# OpenTallas memory compiler (tools/mem_compiler), ASAP7 abstract view
VERSION 5.7 ;
BUSBITCHARS "[]" ;
DIVIDERCHAR "/" ;
PROPERTYDEFINITIONS
  MACRO width INTEGER ;
  MACRO depth INTEGER ;
  MACRO banks INTEGER ;
END PROPERTYDEFINITIONS
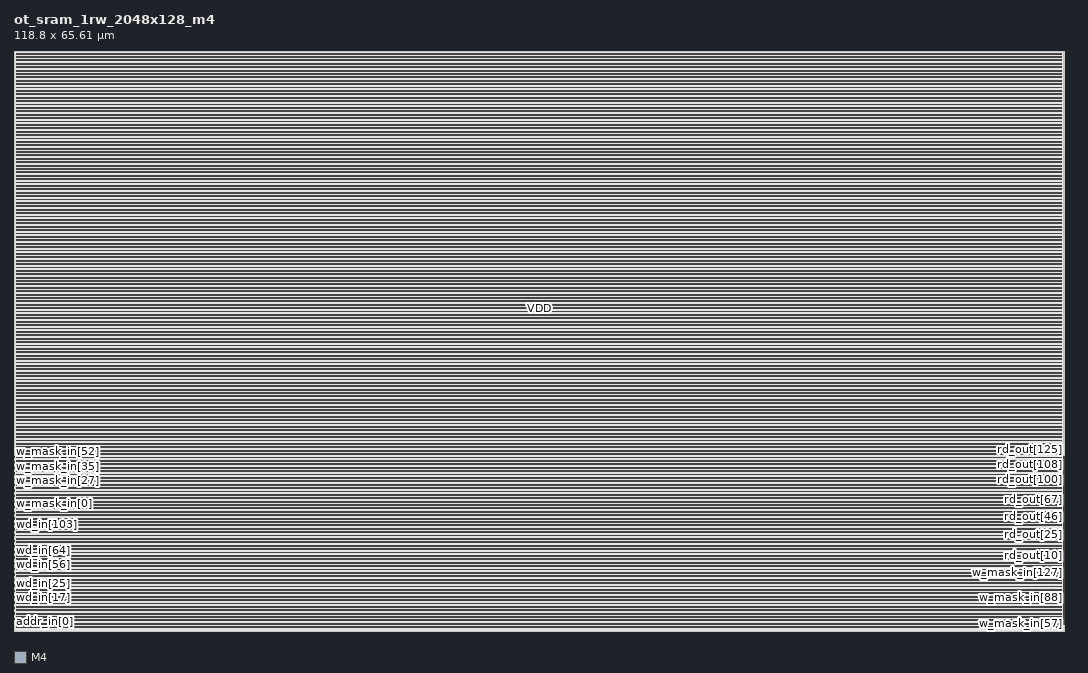
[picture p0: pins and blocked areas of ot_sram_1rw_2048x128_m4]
MACRO ot_sram_1rw_2048x128_m4
  PROPERTY width 128 ;
  PROPERTY depth 2048 ;
  PROPERTY banks 1 ;
  FOREIGN ot_sram_1rw_2048x128_m4 0 0 ;
  SYMMETRY X Y R90 ;
  SIZE 118.800 BY 65.610 ;
  CLASS BLOCK ;
  PIN clk
    DIRECTION INPUT ;
    USE CLOCK ;
    SHAPE ABUTMENT ;
    PORT
      LAYER M4 ;
      RECT 0.000 0.768 0.024 0.792 ;
    END
  END clk
  PIN ce_in
    DIRECTION INPUT ;
    USE SIGNAL ;
    SHAPE ABUTMENT ;
    PORT
      LAYER M4 ;
      RECT 0.000 0.864 0.024 0.888 ;
    END
  END ce_in
  PIN we_in
    DIRECTION INPUT ;
    USE SIGNAL ;
    SHAPE ABUTMENT ;
    PORT
      LAYER M4 ;
      RECT 0.000 0.960 0.024 0.984 ;
    END
  END we_in
  PIN addr_in[0]
    DIRECTION INPUT ;
    USE SIGNAL ;
    SHAPE ABUTMENT ;
    PORT
      LAYER M4 ;
      RECT 0.000 1.056 0.024 1.080 ;
    END
  END addr_in[0]
  PIN addr_in[1]
    DIRECTION INPUT ;
    USE SIGNAL ;
    SHAPE ABUTMENT ;
    PORT
      LAYER M4 ;
      RECT 0.000 1.152 0.024 1.176 ;
    END
  END addr_in[1]
  PIN addr_in[2]
    DIRECTION INPUT ;
    USE SIGNAL ;
    SHAPE ABUTMENT ;
    PORT
      LAYER M4 ;
      RECT 0.000 1.248 0.024 1.272 ;
    END
  END addr_in[2]
  PIN addr_in[3]
    DIRECTION INPUT ;
    USE SIGNAL ;
    SHAPE ABUTMENT ;
    PORT
      LAYER M4 ;
      RECT 0.000 1.344 0.024 1.368 ;
    END
  END addr_in[3]
  PIN addr_in[4]
    DIRECTION INPUT ;
    USE SIGNAL ;
    SHAPE ABUTMENT ;
    PORT
      LAYER M4 ;
      RECT 0.000 1.440 0.024 1.464 ;
    END
  END addr_in[4]
  PIN addr_in[5]
    DIRECTION INPUT ;
    USE SIGNAL ;
    SHAPE ABUTMENT ;
    PORT
      LAYER M4 ;
      RECT 0.000 1.536 0.024 1.560 ;
    END
  END addr_in[5]
  PIN addr_in[6]
    DIRECTION INPUT ;
    USE SIGNAL ;
    SHAPE ABUTMENT ;
    PORT
      LAYER M4 ;
      RECT 0.000 1.632 0.024 1.656 ;
    END
  END addr_in[6]
  PIN addr_in[7]
    DIRECTION INPUT ;
    USE SIGNAL ;
    SHAPE ABUTMENT ;
    PORT
      LAYER M4 ;
      RECT 0.000 1.728 0.024 1.752 ;
    END
  END addr_in[7]
  PIN addr_in[8]
    DIRECTION INPUT ;
    USE SIGNAL ;
    SHAPE ABUTMENT ;
    PORT
      LAYER M4 ;
      RECT 0.000 1.824 0.024 1.848 ;
    END
  END addr_in[8]
  PIN addr_in[9]
    DIRECTION INPUT ;
    USE SIGNAL ;
    SHAPE ABUTMENT ;
    PORT
      LAYER M4 ;
      RECT 0.000 1.920 0.024 1.944 ;
    END
  END addr_in[9]
  PIN addr_in[10]
    DIRECTION INPUT ;
    USE SIGNAL ;
    SHAPE ABUTMENT ;
    PORT
      LAYER M4 ;
      RECT 0.000 2.016 0.024 2.040 ;
    END
  END addr_in[10]
  PIN wd_in[0]
    DIRECTION INPUT ;
    USE SIGNAL ;
    SHAPE ABUTMENT ;
    PORT
      LAYER M4 ;
      RECT 0.000 2.112 0.024 2.136 ;
    END
  END wd_in[0]
  PIN wd_in[1]
    DIRECTION INPUT ;
    USE SIGNAL ;
    SHAPE ABUTMENT ;
    PORT
      LAYER M4 ;
      RECT 0.000 2.208 0.024 2.232 ;
    END
  END wd_in[1]
  PIN wd_in[2]
    DIRECTION INPUT ;
    USE SIGNAL ;
    SHAPE ABUTMENT ;
    PORT
      LAYER M4 ;
      RECT 0.000 2.304 0.024 2.328 ;
    END
  END wd_in[2]
  PIN wd_in[3]
    DIRECTION INPUT ;
    USE SIGNAL ;
    SHAPE ABUTMENT ;
    PORT
      LAYER M4 ;
      RECT 0.000 2.400 0.024 2.424 ;
    END
  END wd_in[3]
  PIN wd_in[4]
    DIRECTION INPUT ;
    USE SIGNAL ;
    SHAPE ABUTMENT ;
    PORT
      LAYER M4 ;
      RECT 0.000 2.496 0.024 2.520 ;
    END
  END wd_in[4]
  PIN wd_in[5]
    DIRECTION INPUT ;
    USE SIGNAL ;
    SHAPE ABUTMENT ;
    PORT
      LAYER M4 ;
      RECT 0.000 2.592 0.024 2.616 ;
    END
  END wd_in[5]
  PIN wd_in[6]
    DIRECTION INPUT ;
    USE SIGNAL ;
    SHAPE ABUTMENT ;
    PORT
      LAYER M4 ;
      RECT 0.000 2.688 0.024 2.712 ;
    END
  END wd_in[6]
  PIN wd_in[7]
    DIRECTION INPUT ;
    USE SIGNAL ;
    SHAPE ABUTMENT ;
    PORT
      LAYER M4 ;
      RECT 0.000 2.784 0.024 2.808 ;
    END
  END wd_in[7]
  PIN wd_in[8]
    DIRECTION INPUT ;
    USE SIGNAL ;
    SHAPE ABUTMENT ;
    PORT
      LAYER M4 ;
      RECT 0.000 2.880 0.024 2.904 ;
    END
  END wd_in[8]
  PIN wd_in[9]
    DIRECTION INPUT ;
    USE SIGNAL ;
    SHAPE ABUTMENT ;
    PORT
      LAYER M4 ;
      RECT 0.000 2.976 0.024 3.000 ;
    END
  END wd_in[9]
  PIN wd_in[10]
    DIRECTION INPUT ;
    USE SIGNAL ;
    SHAPE ABUTMENT ;
    PORT
      LAYER M4 ;
      RECT 0.000 3.072 0.024 3.096 ;
    END
  END wd_in[10]
  PIN wd_in[11]
    DIRECTION INPUT ;
    USE SIGNAL ;
    SHAPE ABUTMENT ;
    PORT
      LAYER M4 ;
      RECT 0.000 3.168 0.024 3.192 ;
    END
  END wd_in[11]
  PIN wd_in[12]
    DIRECTION INPUT ;
    USE SIGNAL ;
    SHAPE ABUTMENT ;
    PORT
      LAYER M4 ;
      RECT 0.000 3.264 0.024 3.288 ;
    END
  END wd_in[12]
  PIN wd_in[13]
    DIRECTION INPUT ;
    USE SIGNAL ;
    SHAPE ABUTMENT ;
    PORT
      LAYER M4 ;
      RECT 0.000 3.360 0.024 3.384 ;
    END
  END wd_in[13]
  PIN wd_in[14]
    DIRECTION INPUT ;
    USE SIGNAL ;
    SHAPE ABUTMENT ;
    PORT
      LAYER M4 ;
      RECT 0.000 3.456 0.024 3.480 ;
    END
  END wd_in[14]
  PIN wd_in[15]
    DIRECTION INPUT ;
    USE SIGNAL ;
    SHAPE ABUTMENT ;
    PORT
      LAYER M4 ;
      RECT 0.000 3.552 0.024 3.576 ;
    END
  END wd_in[15]
  PIN wd_in[16]
    DIRECTION INPUT ;
    USE SIGNAL ;
    SHAPE ABUTMENT ;
    PORT
      LAYER M4 ;
      RECT 0.000 3.648 0.024 3.672 ;
    END
  END wd_in[16]
  PIN wd_in[17]
    DIRECTION INPUT ;
    USE SIGNAL ;
    SHAPE ABUTMENT ;
    PORT
      LAYER M4 ;
      RECT 0.000 3.744 0.024 3.768 ;
    END
  END wd_in[17]
  PIN wd_in[18]
    DIRECTION INPUT ;
    USE SIGNAL ;
    SHAPE ABUTMENT ;
    PORT
      LAYER M4 ;
      RECT 0.000 3.840 0.024 3.864 ;
    END
  END wd_in[18]
  PIN wd_in[19]
    DIRECTION INPUT ;
    USE SIGNAL ;
    SHAPE ABUTMENT ;
    PORT
      LAYER M4 ;
      RECT 0.000 3.936 0.024 3.960 ;
    END
  END wd_in[19]
  PIN wd_in[20]
    DIRECTION INPUT ;
    USE SIGNAL ;
    SHAPE ABUTMENT ;
    PORT
      LAYER M4 ;
      RECT 0.000 4.032 0.024 4.056 ;
    END
  END wd_in[20]
  PIN wd_in[21]
    DIRECTION INPUT ;
    USE SIGNAL ;
    SHAPE ABUTMENT ;
    PORT
      LAYER M4 ;
      RECT 0.000 4.128 0.024 4.152 ;
    END
  END wd_in[21]
  PIN wd_in[22]
    DIRECTION INPUT ;
    USE SIGNAL ;
    SHAPE ABUTMENT ;
    PORT
      LAYER M4 ;
      RECT 0.000 4.224 0.024 4.248 ;
    END
  END wd_in[22]
  PIN wd_in[23]
    DIRECTION INPUT ;
    USE SIGNAL ;
    SHAPE ABUTMENT ;
    PORT
      LAYER M4 ;
      RECT 0.000 4.320 0.024 4.344 ;
    END
  END wd_in[23]
  PIN wd_in[24]
    DIRECTION INPUT ;
    USE SIGNAL ;
    SHAPE ABUTMENT ;
    PORT
      LAYER M4 ;
      RECT 0.000 4.416 0.024 4.440 ;
    END
  END wd_in[24]
  PIN wd_in[25]
    DIRECTION INPUT ;
    USE SIGNAL ;
    SHAPE ABUTMENT ;
    PORT
      LAYER M4 ;
      RECT 0.000 4.512 0.024 4.536 ;
    END
  END wd_in[25]
  PIN wd_in[26]
    DIRECTION INPUT ;
    USE SIGNAL ;
    SHAPE ABUTMENT ;
    PORT
      LAYER M4 ;
      RECT 0.000 4.608 0.024 4.632 ;
    END
  END wd_in[26]
  PIN wd_in[27]
    DIRECTION INPUT ;
    USE SIGNAL ;
    SHAPE ABUTMENT ;
    PORT
      LAYER M4 ;
      RECT 0.000 4.704 0.024 4.728 ;
    END
  END wd_in[27]
  PIN wd_in[28]
    DIRECTION INPUT ;
    USE SIGNAL ;
    SHAPE ABUTMENT ;
    PORT
      LAYER M4 ;
      RECT 0.000 4.800 0.024 4.824 ;
    END
  END wd_in[28]
  PIN wd_in[29]
    DIRECTION INPUT ;
    USE SIGNAL ;
    SHAPE ABUTMENT ;
    PORT
      LAYER M4 ;
      RECT 0.000 4.896 0.024 4.920 ;
    END
  END wd_in[29]
  PIN wd_in[30]
    DIRECTION INPUT ;
    USE SIGNAL ;
    SHAPE ABUTMENT ;
    PORT
      LAYER M4 ;
      RECT 0.000 4.992 0.024 5.016 ;
    END
  END wd_in[30]
  PIN wd_in[31]
    DIRECTION INPUT ;
    USE SIGNAL ;
    SHAPE ABUTMENT ;
    PORT
      LAYER M4 ;
      RECT 0.000 5.088 0.024 5.112 ;
    END
  END wd_in[31]
  PIN wd_in[32]
    DIRECTION INPUT ;
    USE SIGNAL ;
    SHAPE ABUTMENT ;
    PORT
      LAYER M4 ;
      RECT 0.000 5.184 0.024 5.208 ;
    END
  END wd_in[32]
  PIN wd_in[33]
    DIRECTION INPUT ;
    USE SIGNAL ;
    SHAPE ABUTMENT ;
    PORT
      LAYER M4 ;
      RECT 0.000 5.280 0.024 5.304 ;
    END
  END wd_in[33]
  PIN wd_in[34]
    DIRECTION INPUT ;
    USE SIGNAL ;
    SHAPE ABUTMENT ;
    PORT
      LAYER M4 ;
      RECT 0.000 5.376 0.024 5.400 ;
    END
  END wd_in[34]
  PIN wd_in[35]
    DIRECTION INPUT ;
    USE SIGNAL ;
    SHAPE ABUTMENT ;
    PORT
      LAYER M4 ;
      RECT 0.000 5.472 0.024 5.496 ;
    END
  END wd_in[35]
  PIN wd_in[36]
    DIRECTION INPUT ;
    USE SIGNAL ;
    SHAPE ABUTMENT ;
    PORT
      LAYER M4 ;
      RECT 0.000 5.568 0.024 5.592 ;
    END
  END wd_in[36]
  PIN wd_in[37]
    DIRECTION INPUT ;
    USE SIGNAL ;
    SHAPE ABUTMENT ;
    PORT
      LAYER M4 ;
      RECT 0.000 5.664 0.024 5.688 ;
    END
  END wd_in[37]
  PIN wd_in[38]
    DIRECTION INPUT ;
    USE SIGNAL ;
    SHAPE ABUTMENT ;
    PORT
      LAYER M4 ;
      RECT 0.000 5.760 0.024 5.784 ;
    END
  END wd_in[38]
  PIN wd_in[39]
    DIRECTION INPUT ;
    USE SIGNAL ;
    SHAPE ABUTMENT ;
    PORT
      LAYER M4 ;
      RECT 0.000 5.856 0.024 5.880 ;
    END
  END wd_in[39]
  PIN wd_in[40]
    DIRECTION INPUT ;
    USE SIGNAL ;
    SHAPE ABUTMENT ;
    PORT
      LAYER M4 ;
      RECT 0.000 5.952 0.024 5.976 ;
    END
  END wd_in[40]
  PIN wd_in[41]
    DIRECTION INPUT ;
    USE SIGNAL ;
    SHAPE ABUTMENT ;
    PORT
      LAYER M4 ;
      RECT 0.000 6.048 0.024 6.072 ;
    END
  END wd_in[41]
  PIN wd_in[42]
    DIRECTION INPUT ;
    USE SIGNAL ;
    SHAPE ABUTMENT ;
    PORT
      LAYER M4 ;
      RECT 0.000 6.144 0.024 6.168 ;
    END
  END wd_in[42]
  PIN wd_in[43]
    DIRECTION INPUT ;
    USE SIGNAL ;
    SHAPE ABUTMENT ;
    PORT
      LAYER M4 ;
      RECT 0.000 6.240 0.024 6.264 ;
    END
  END wd_in[43]
  PIN wd_in[44]
    DIRECTION INPUT ;
    USE SIGNAL ;
    SHAPE ABUTMENT ;
    PORT
      LAYER M4 ;
      RECT 0.000 6.336 0.024 6.360 ;
    END
  END wd_in[44]
  PIN wd_in[45]
    DIRECTION INPUT ;
    USE SIGNAL ;
    SHAPE ABUTMENT ;
    PORT
      LAYER M4 ;
      RECT 0.000 6.432 0.024 6.456 ;
    END
  END wd_in[45]
  PIN wd_in[46]
    DIRECTION INPUT ;
    USE SIGNAL ;
    SHAPE ABUTMENT ;
    PORT
      LAYER M4 ;
      RECT 0.000 6.528 0.024 6.552 ;
    END
  END wd_in[46]
  PIN wd_in[47]
    DIRECTION INPUT ;
    USE SIGNAL ;
    SHAPE ABUTMENT ;
    PORT
      LAYER M4 ;
      RECT 0.000 6.624 0.024 6.648 ;
    END
  END wd_in[47]
  PIN wd_in[48]
    DIRECTION INPUT ;
    USE SIGNAL ;
    SHAPE ABUTMENT ;
    PORT
      LAYER M4 ;
      RECT 0.000 6.720 0.024 6.744 ;
    END
  END wd_in[48]
  PIN wd_in[49]
    DIRECTION INPUT ;
    USE SIGNAL ;
    SHAPE ABUTMENT ;
    PORT
      LAYER M4 ;
      RECT 0.000 6.816 0.024 6.840 ;
    END
  END wd_in[49]
  PIN wd_in[50]
    DIRECTION INPUT ;
    USE SIGNAL ;
    SHAPE ABUTMENT ;
    PORT
      LAYER M4 ;
      RECT 0.000 6.912 0.024 6.936 ;
    END
  END wd_in[50]
  PIN wd_in[51]
    DIRECTION INPUT ;
    USE SIGNAL ;
    SHAPE ABUTMENT ;
    PORT
      LAYER M4 ;
      RECT 0.000 7.008 0.024 7.032 ;
    END
  END wd_in[51]
  PIN wd_in[52]
    DIRECTION INPUT ;
    USE SIGNAL ;
    SHAPE ABUTMENT ;
    PORT
      LAYER M4 ;
      RECT 0.000 7.104 0.024 7.128 ;
    END
  END wd_in[52]
  PIN wd_in[53]
    DIRECTION INPUT ;
    USE SIGNAL ;
    SHAPE ABUTMENT ;
    PORT
      LAYER M4 ;
      RECT 0.000 7.200 0.024 7.224 ;
    END
  END wd_in[53]
  PIN wd_in[54]
    DIRECTION INPUT ;
    USE SIGNAL ;
    SHAPE ABUTMENT ;
    PORT
      LAYER M4 ;
      RECT 0.000 7.296 0.024 7.320 ;
    END
  END wd_in[54]
  PIN wd_in[55]
    DIRECTION INPUT ;
    USE SIGNAL ;
    SHAPE ABUTMENT ;
    PORT
      LAYER M4 ;
      RECT 0.000 7.392 0.024 7.416 ;
    END
  END wd_in[55]
  PIN wd_in[56]
    DIRECTION INPUT ;
    USE SIGNAL ;
    SHAPE ABUTMENT ;
    PORT
      LAYER M4 ;
      RECT 0.000 7.488 0.024 7.512 ;
    END
  END wd_in[56]
  PIN wd_in[57]
    DIRECTION INPUT ;
    USE SIGNAL ;
    SHAPE ABUTMENT ;
    PORT
      LAYER M4 ;
      RECT 0.000 7.584 0.024 7.608 ;
    END
  END wd_in[57]
  PIN wd_in[58]
    DIRECTION INPUT ;
    USE SIGNAL ;
    SHAPE ABUTMENT ;
    PORT
      LAYER M4 ;
      RECT 0.000 7.680 0.024 7.704 ;
    END
  END wd_in[58]
  PIN wd_in[59]
    DIRECTION INPUT ;
    USE SIGNAL ;
    SHAPE ABUTMENT ;
    PORT
      LAYER M4 ;
      RECT 0.000 7.776 0.024 7.800 ;
    END
  END wd_in[59]
  PIN wd_in[60]
    DIRECTION INPUT ;
    USE SIGNAL ;
    SHAPE ABUTMENT ;
    PORT
      LAYER M4 ;
      RECT 0.000 7.872 0.024 7.896 ;
    END
  END wd_in[60]
  PIN wd_in[61]
    DIRECTION INPUT ;
    USE SIGNAL ;
    SHAPE ABUTMENT ;
    PORT
      LAYER M4 ;
      RECT 0.000 7.968 0.024 7.992 ;
    END
  END wd_in[61]
  PIN wd_in[62]
    DIRECTION INPUT ;
    USE SIGNAL ;
    SHAPE ABUTMENT ;
    PORT
      LAYER M4 ;
      RECT 0.000 8.064 0.024 8.088 ;
    END
  END wd_in[62]
  PIN wd_in[63]
    DIRECTION INPUT ;
    USE SIGNAL ;
    SHAPE ABUTMENT ;
    PORT
      LAYER M4 ;
      RECT 0.000 8.160 0.024 8.184 ;
    END
  END wd_in[63]
  PIN wd_in[64]
    DIRECTION INPUT ;
    USE SIGNAL ;
    SHAPE ABUTMENT ;
    PORT
      LAYER M4 ;
      RECT 0.000 8.256 0.024 8.280 ;
    END
  END wd_in[64]
  PIN wd_in[65]
    DIRECTION INPUT ;
    USE SIGNAL ;
    SHAPE ABUTMENT ;
    PORT
      LAYER M4 ;
      RECT 0.000 8.352 0.024 8.376 ;
    END
  END wd_in[65]
  PIN wd_in[66]
    DIRECTION INPUT ;
    USE SIGNAL ;
    SHAPE ABUTMENT ;
    PORT
      LAYER M4 ;
      RECT 0.000 8.448 0.024 8.472 ;
    END
  END wd_in[66]
  PIN wd_in[67]
    DIRECTION INPUT ;
    USE SIGNAL ;
    SHAPE ABUTMENT ;
    PORT
      LAYER M4 ;
      RECT 0.000 8.544 0.024 8.568 ;
    END
  END wd_in[67]
  PIN wd_in[68]
    DIRECTION INPUT ;
    USE SIGNAL ;
    SHAPE ABUTMENT ;
    PORT
      LAYER M4 ;
      RECT 0.000 8.640 0.024 8.664 ;
    END
  END wd_in[68]
  PIN wd_in[69]
    DIRECTION INPUT ;
    USE SIGNAL ;
    SHAPE ABUTMENT ;
    PORT
      LAYER M4 ;
      RECT 0.000 8.736 0.024 8.760 ;
    END
  END wd_in[69]
  PIN wd_in[70]
    DIRECTION INPUT ;
    USE SIGNAL ;
    SHAPE ABUTMENT ;
    PORT
      LAYER M4 ;
      RECT 0.000 8.832 0.024 8.856 ;
    END
  END wd_in[70]
  PIN wd_in[71]
    DIRECTION INPUT ;
    USE SIGNAL ;
    SHAPE ABUTMENT ;
    PORT
      LAYER M4 ;
      RECT 0.000 8.928 0.024 8.952 ;
    END
  END wd_in[71]
  PIN wd_in[72]
    DIRECTION INPUT ;
    USE SIGNAL ;
    SHAPE ABUTMENT ;
    PORT
      LAYER M4 ;
      RECT 0.000 9.024 0.024 9.048 ;
    END
  END wd_in[72]
  PIN wd_in[73]
    DIRECTION INPUT ;
    USE SIGNAL ;
    SHAPE ABUTMENT ;
    PORT
      LAYER M4 ;
      RECT 0.000 9.120 0.024 9.144 ;
    END
  END wd_in[73]
  PIN wd_in[74]
    DIRECTION INPUT ;
    USE SIGNAL ;
    SHAPE ABUTMENT ;
    PORT
      LAYER M4 ;
      RECT 0.000 9.216 0.024 9.240 ;
    END
  END wd_in[74]
  PIN wd_in[75]
    DIRECTION INPUT ;
    USE SIGNAL ;
    SHAPE ABUTMENT ;
    PORT
      LAYER M4 ;
      RECT 0.000 9.312 0.024 9.336 ;
    END
  END wd_in[75]
  PIN wd_in[76]
    DIRECTION INPUT ;
    USE SIGNAL ;
    SHAPE ABUTMENT ;
    PORT
      LAYER M4 ;
      RECT 0.000 9.408 0.024 9.432 ;
    END
  END wd_in[76]
  PIN wd_in[77]
    DIRECTION INPUT ;
    USE SIGNAL ;
    SHAPE ABUTMENT ;
    PORT
      LAYER M4 ;
      RECT 0.000 9.504 0.024 9.528 ;
    END
  END wd_in[77]
  PIN wd_in[78]
    DIRECTION INPUT ;
    USE SIGNAL ;
    SHAPE ABUTMENT ;
    PORT
      LAYER M4 ;
      RECT 0.000 9.600 0.024 9.624 ;
    END
  END wd_in[78]
  PIN wd_in[79]
    DIRECTION INPUT ;
    USE SIGNAL ;
    SHAPE ABUTMENT ;
    PORT
      LAYER M4 ;
      RECT 0.000 9.696 0.024 9.720 ;
    END
  END wd_in[79]
  PIN wd_in[80]
    DIRECTION INPUT ;
    USE SIGNAL ;
    SHAPE ABUTMENT ;
    PORT
      LAYER M4 ;
      RECT 0.000 9.792 0.024 9.816 ;
    END
  END wd_in[80]
  PIN wd_in[81]
    DIRECTION INPUT ;
    USE SIGNAL ;
    SHAPE ABUTMENT ;
    PORT
      LAYER M4 ;
      RECT 0.000 9.888 0.024 9.912 ;
    END
  END wd_in[81]
  PIN wd_in[82]
    DIRECTION INPUT ;
    USE SIGNAL ;
    SHAPE ABUTMENT ;
    PORT
      LAYER M4 ;
      RECT 0.000 9.984 0.024 10.008 ;
    END
  END wd_in[82]
  PIN wd_in[83]
    DIRECTION INPUT ;
    USE SIGNAL ;
    SHAPE ABUTMENT ;
    PORT
      LAYER M4 ;
      RECT 0.000 10.080 0.024 10.104 ;
    END
  END wd_in[83]
  PIN wd_in[84]
    DIRECTION INPUT ;
    USE SIGNAL ;
    SHAPE ABUTMENT ;
    PORT
      LAYER M4 ;
      RECT 0.000 10.176 0.024 10.200 ;
    END
  END wd_in[84]
  PIN wd_in[85]
    DIRECTION INPUT ;
    USE SIGNAL ;
    SHAPE ABUTMENT ;
    PORT
      LAYER M4 ;
      RECT 0.000 10.272 0.024 10.296 ;
    END
  END wd_in[85]
  PIN wd_in[86]
    DIRECTION INPUT ;
    USE SIGNAL ;
    SHAPE ABUTMENT ;
    PORT
      LAYER M4 ;
      RECT 0.000 10.368 0.024 10.392 ;
    END
  END wd_in[86]
  PIN wd_in[87]
    DIRECTION INPUT ;
    USE SIGNAL ;
    SHAPE ABUTMENT ;
    PORT
      LAYER M4 ;
      RECT 0.000 10.464 0.024 10.488 ;
    END
  END wd_in[87]
  PIN wd_in[88]
    DIRECTION INPUT ;
    USE SIGNAL ;
    SHAPE ABUTMENT ;
    PORT
      LAYER M4 ;
      RECT 0.000 10.560 0.024 10.584 ;
    END
  END wd_in[88]
  PIN wd_in[89]
    DIRECTION INPUT ;
    USE SIGNAL ;
    SHAPE ABUTMENT ;
    PORT
      LAYER M4 ;
      RECT 0.000 10.656 0.024 10.680 ;
    END
  END wd_in[89]
  PIN wd_in[90]
    DIRECTION INPUT ;
    USE SIGNAL ;
    SHAPE ABUTMENT ;
    PORT
      LAYER M4 ;
      RECT 0.000 10.752 0.024 10.776 ;
    END
  END wd_in[90]
  PIN wd_in[91]
    DIRECTION INPUT ;
    USE SIGNAL ;
    SHAPE ABUTMENT ;
    PORT
      LAYER M4 ;
      RECT 0.000 10.848 0.024 10.872 ;
    END
  END wd_in[91]
  PIN wd_in[92]
    DIRECTION INPUT ;
    USE SIGNAL ;
    SHAPE ABUTMENT ;
    PORT
      LAYER M4 ;
      RECT 0.000 10.944 0.024 10.968 ;
    END
  END wd_in[92]
  PIN wd_in[93]
    DIRECTION INPUT ;
    USE SIGNAL ;
    SHAPE ABUTMENT ;
    PORT
      LAYER M4 ;
      RECT 0.000 11.040 0.024 11.064 ;
    END
  END wd_in[93]
  PIN wd_in[94]
    DIRECTION INPUT ;
    USE SIGNAL ;
    SHAPE ABUTMENT ;
    PORT
      LAYER M4 ;
      RECT 0.000 11.136 0.024 11.160 ;
    END
  END wd_in[94]
  PIN wd_in[95]
    DIRECTION INPUT ;
    USE SIGNAL ;
    SHAPE ABUTMENT ;
    PORT
      LAYER M4 ;
      RECT 0.000 11.232 0.024 11.256 ;
    END
  END wd_in[95]
  PIN wd_in[96]
    DIRECTION INPUT ;
    USE SIGNAL ;
    SHAPE ABUTMENT ;
    PORT
      LAYER M4 ;
      RECT 0.000 11.328 0.024 11.352 ;
    END
  END wd_in[96]
  PIN wd_in[97]
    DIRECTION INPUT ;
    USE SIGNAL ;
    SHAPE ABUTMENT ;
    PORT
      LAYER M4 ;
      RECT 0.000 11.424 0.024 11.448 ;
    END
  END wd_in[97]
  PIN wd_in[98]
    DIRECTION INPUT ;
    USE SIGNAL ;
    SHAPE ABUTMENT ;
    PORT
      LAYER M4 ;
      RECT 0.000 11.520 0.024 11.544 ;
    END
  END wd_in[98]
  PIN wd_in[99]
    DIRECTION INPUT ;
    USE SIGNAL ;
    SHAPE ABUTMENT ;
    PORT
      LAYER M4 ;
      RECT 0.000 11.616 0.024 11.640 ;
    END
  END wd_in[99]
  PIN wd_in[100]
    DIRECTION INPUT ;
    USE SIGNAL ;
    SHAPE ABUTMENT ;
    PORT
      LAYER M4 ;
      RECT 0.000 11.712 0.024 11.736 ;
    END
  END wd_in[100]
  PIN wd_in[101]
    DIRECTION INPUT ;
    USE SIGNAL ;
    SHAPE ABUTMENT ;
    PORT
      LAYER M4 ;
      RECT 0.000 11.808 0.024 11.832 ;
    END
  END wd_in[101]
  PIN wd_in[102]
    DIRECTION INPUT ;
    USE SIGNAL ;
    SHAPE ABUTMENT ;
    PORT
      LAYER M4 ;
      RECT 0.000 11.904 0.024 11.928 ;
    END
  END wd_in[102]
  PIN wd_in[103]
    DIRECTION INPUT ;
    USE SIGNAL ;
    SHAPE ABUTMENT ;
    PORT
      LAYER M4 ;
      RECT 0.000 12.000 0.024 12.024 ;
    END
  END wd_in[103]
  PIN wd_in[104]
    DIRECTION INPUT ;
    USE SIGNAL ;
    SHAPE ABUTMENT ;
    PORT
      LAYER M4 ;
      RECT 0.000 12.096 0.024 12.120 ;
    END
  END wd_in[104]
  PIN wd_in[105]
    DIRECTION INPUT ;
    USE SIGNAL ;
    SHAPE ABUTMENT ;
    PORT
      LAYER M4 ;
      RECT 0.000 12.192 0.024 12.216 ;
    END
  END wd_in[105]
  PIN wd_in[106]
    DIRECTION INPUT ;
    USE SIGNAL ;
    SHAPE ABUTMENT ;
    PORT
      LAYER M4 ;
      RECT 0.000 12.288 0.024 12.312 ;
    END
  END wd_in[106]
  PIN wd_in[107]
    DIRECTION INPUT ;
    USE SIGNAL ;
    SHAPE ABUTMENT ;
    PORT
      LAYER M4 ;
      RECT 0.000 12.384 0.024 12.408 ;
    END
  END wd_in[107]
  PIN wd_in[108]
    DIRECTION INPUT ;
    USE SIGNAL ;
    SHAPE ABUTMENT ;
    PORT
      LAYER M4 ;
      RECT 0.000 12.480 0.024 12.504 ;
    END
  END wd_in[108]
  PIN wd_in[109]
    DIRECTION INPUT ;
    USE SIGNAL ;
    SHAPE ABUTMENT ;
    PORT
      LAYER M4 ;
      RECT 0.000 12.576 0.024 12.600 ;
    END
  END wd_in[109]
  PIN wd_in[110]
    DIRECTION INPUT ;
    USE SIGNAL ;
    SHAPE ABUTMENT ;
    PORT
      LAYER M4 ;
      RECT 0.000 12.672 0.024 12.696 ;
    END
  END wd_in[110]
  PIN wd_in[111]
    DIRECTION INPUT ;
    USE SIGNAL ;
    SHAPE ABUTMENT ;
    PORT
      LAYER M4 ;
      RECT 0.000 12.768 0.024 12.792 ;
    END
  END wd_in[111]
  PIN wd_in[112]
    DIRECTION INPUT ;
    USE SIGNAL ;
    SHAPE ABUTMENT ;
    PORT
      LAYER M4 ;
      RECT 0.000 12.864 0.024 12.888 ;
    END
  END wd_in[112]
  PIN wd_in[113]
    DIRECTION INPUT ;
    USE SIGNAL ;
    SHAPE ABUTMENT ;
    PORT
      LAYER M4 ;
      RECT 0.000 12.960 0.024 12.984 ;
    END
  END wd_in[113]
  PIN wd_in[114]
    DIRECTION INPUT ;
    USE SIGNAL ;
    SHAPE ABUTMENT ;
    PORT
      LAYER M4 ;
      RECT 0.000 13.056 0.024 13.080 ;
    END
  END wd_in[114]
  PIN wd_in[115]
    DIRECTION INPUT ;
    USE SIGNAL ;
    SHAPE ABUTMENT ;
    PORT
      LAYER M4 ;
      RECT 0.000 13.152 0.024 13.176 ;
    END
  END wd_in[115]
  PIN wd_in[116]
    DIRECTION INPUT ;
    USE SIGNAL ;
    SHAPE ABUTMENT ;
    PORT
      LAYER M4 ;
      RECT 0.000 13.248 0.024 13.272 ;
    END
  END wd_in[116]
  PIN wd_in[117]
    DIRECTION INPUT ;
    USE SIGNAL ;
    SHAPE ABUTMENT ;
    PORT
      LAYER M4 ;
      RECT 0.000 13.344 0.024 13.368 ;
    END
  END wd_in[117]
  PIN wd_in[118]
    DIRECTION INPUT ;
    USE SIGNAL ;
    SHAPE ABUTMENT ;
    PORT
      LAYER M4 ;
      RECT 0.000 13.440 0.024 13.464 ;
    END
  END wd_in[118]
  PIN wd_in[119]
    DIRECTION INPUT ;
    USE SIGNAL ;
    SHAPE ABUTMENT ;
    PORT
      LAYER M4 ;
      RECT 0.000 13.536 0.024 13.560 ;
    END
  END wd_in[119]
  PIN wd_in[120]
    DIRECTION INPUT ;
    USE SIGNAL ;
    SHAPE ABUTMENT ;
    PORT
      LAYER M4 ;
      RECT 0.000 13.632 0.024 13.656 ;
    END
  END wd_in[120]
  PIN wd_in[121]
    DIRECTION INPUT ;
    USE SIGNAL ;
    SHAPE ABUTMENT ;
    PORT
      LAYER M4 ;
      RECT 0.000 13.728 0.024 13.752 ;
    END
  END wd_in[121]
  PIN wd_in[122]
    DIRECTION INPUT ;
    USE SIGNAL ;
    SHAPE ABUTMENT ;
    PORT
      LAYER M4 ;
      RECT 0.000 13.824 0.024 13.848 ;
    END
  END wd_in[122]
  PIN wd_in[123]
    DIRECTION INPUT ;
    USE SIGNAL ;
    SHAPE ABUTMENT ;
    PORT
      LAYER M4 ;
      RECT 0.000 13.920 0.024 13.944 ;
    END
  END wd_in[123]
  PIN wd_in[124]
    DIRECTION INPUT ;
    USE SIGNAL ;
    SHAPE ABUTMENT ;
    PORT
      LAYER M4 ;
      RECT 0.000 14.016 0.024 14.040 ;
    END
  END wd_in[124]
  PIN wd_in[125]
    DIRECTION INPUT ;
    USE SIGNAL ;
    SHAPE ABUTMENT ;
    PORT
      LAYER M4 ;
      RECT 0.000 14.112 0.024 14.136 ;
    END
  END wd_in[125]
  PIN wd_in[126]
    DIRECTION INPUT ;
    USE SIGNAL ;
    SHAPE ABUTMENT ;
    PORT
      LAYER M4 ;
      RECT 0.000 14.208 0.024 14.232 ;
    END
  END wd_in[126]
  PIN wd_in[127]
    DIRECTION INPUT ;
    USE SIGNAL ;
    SHAPE ABUTMENT ;
    PORT
      LAYER M4 ;
      RECT 0.000 14.304 0.024 14.328 ;
    END
  END wd_in[127]
  PIN w_mask_in[0]
    DIRECTION INPUT ;
    USE SIGNAL ;
    SHAPE ABUTMENT ;
    PORT
      LAYER M4 ;
      RECT 0.000 14.400 0.024 14.424 ;
    END
  END w_mask_in[0]
  PIN w_mask_in[1]
    DIRECTION INPUT ;
    USE SIGNAL ;
    SHAPE ABUTMENT ;
    PORT
      LAYER M4 ;
      RECT 0.000 14.496 0.024 14.520 ;
    END
  END w_mask_in[1]
  PIN w_mask_in[2]
    DIRECTION INPUT ;
    USE SIGNAL ;
    SHAPE ABUTMENT ;
    PORT
      LAYER M4 ;
      RECT 0.000 14.592 0.024 14.616 ;
    END
  END w_mask_in[2]
  PIN w_mask_in[3]
    DIRECTION INPUT ;
    USE SIGNAL ;
    SHAPE ABUTMENT ;
    PORT
      LAYER M4 ;
      RECT 0.000 14.688 0.024 14.712 ;
    END
  END w_mask_in[3]
  PIN w_mask_in[4]
    DIRECTION INPUT ;
    USE SIGNAL ;
    SHAPE ABUTMENT ;
    PORT
      LAYER M4 ;
      RECT 0.000 14.784 0.024 14.808 ;
    END
  END w_mask_in[4]
  PIN w_mask_in[5]
    DIRECTION INPUT ;
    USE SIGNAL ;
    SHAPE ABUTMENT ;
    PORT
      LAYER M4 ;
      RECT 0.000 14.880 0.024 14.904 ;
    END
  END w_mask_in[5]
  PIN w_mask_in[6]
    DIRECTION INPUT ;
    USE SIGNAL ;
    SHAPE ABUTMENT ;
    PORT
      LAYER M4 ;
      RECT 0.000 14.976 0.024 15.000 ;
    END
  END w_mask_in[6]
  PIN w_mask_in[7]
    DIRECTION INPUT ;
    USE SIGNAL ;
    SHAPE ABUTMENT ;
    PORT
      LAYER M4 ;
      RECT 0.000 15.072 0.024 15.096 ;
    END
  END w_mask_in[7]
  PIN w_mask_in[8]
    DIRECTION INPUT ;
    USE SIGNAL ;
    SHAPE ABUTMENT ;
    PORT
      LAYER M4 ;
      RECT 0.000 15.168 0.024 15.192 ;
    END
  END w_mask_in[8]
  PIN w_mask_in[9]
    DIRECTION INPUT ;
    USE SIGNAL ;
    SHAPE ABUTMENT ;
    PORT
      LAYER M4 ;
      RECT 0.000 15.264 0.024 15.288 ;
    END
  END w_mask_in[9]
  PIN w_mask_in[10]
    DIRECTION INPUT ;
    USE SIGNAL ;
    SHAPE ABUTMENT ;
    PORT
      LAYER M4 ;
      RECT 0.000 15.360 0.024 15.384 ;
    END
  END w_mask_in[10]
  PIN w_mask_in[11]
    DIRECTION INPUT ;
    USE SIGNAL ;
    SHAPE ABUTMENT ;
    PORT
      LAYER M4 ;
      RECT 0.000 15.456 0.024 15.480 ;
    END
  END w_mask_in[11]
  PIN w_mask_in[12]
    DIRECTION INPUT ;
    USE SIGNAL ;
    SHAPE ABUTMENT ;
    PORT
      LAYER M4 ;
      RECT 0.000 15.552 0.024 15.576 ;
    END
  END w_mask_in[12]
  PIN w_mask_in[13]
    DIRECTION INPUT ;
    USE SIGNAL ;
    SHAPE ABUTMENT ;
    PORT
      LAYER M4 ;
      RECT 0.000 15.648 0.024 15.672 ;
    END
  END w_mask_in[13]
  PIN w_mask_in[14]
    DIRECTION INPUT ;
    USE SIGNAL ;
    SHAPE ABUTMENT ;
    PORT
      LAYER M4 ;
      RECT 0.000 15.744 0.024 15.768 ;
    END
  END w_mask_in[14]
  PIN w_mask_in[15]
    DIRECTION INPUT ;
    USE SIGNAL ;
    SHAPE ABUTMENT ;
    PORT
      LAYER M4 ;
      RECT 0.000 15.840 0.024 15.864 ;
    END
  END w_mask_in[15]
  PIN w_mask_in[16]
    DIRECTION INPUT ;
    USE SIGNAL ;
    SHAPE ABUTMENT ;
    PORT
      LAYER M4 ;
      RECT 0.000 15.936 0.024 15.960 ;
    END
  END w_mask_in[16]
  PIN w_mask_in[17]
    DIRECTION INPUT ;
    USE SIGNAL ;
    SHAPE ABUTMENT ;
    PORT
      LAYER M4 ;
      RECT 0.000 16.032 0.024 16.056 ;
    END
  END w_mask_in[17]
  PIN w_mask_in[18]
    DIRECTION INPUT ;
    USE SIGNAL ;
    SHAPE ABUTMENT ;
    PORT
      LAYER M4 ;
      RECT 0.000 16.128 0.024 16.152 ;
    END
  END w_mask_in[18]
  PIN w_mask_in[19]
    DIRECTION INPUT ;
    USE SIGNAL ;
    SHAPE ABUTMENT ;
    PORT
      LAYER M4 ;
      RECT 0.000 16.224 0.024 16.248 ;
    END
  END w_mask_in[19]
  PIN w_mask_in[20]
    DIRECTION INPUT ;
    USE SIGNAL ;
    SHAPE ABUTMENT ;
    PORT
      LAYER M4 ;
      RECT 0.000 16.320 0.024 16.344 ;
    END
  END w_mask_in[20]
  PIN w_mask_in[21]
    DIRECTION INPUT ;
    USE SIGNAL ;
    SHAPE ABUTMENT ;
    PORT
      LAYER M4 ;
      RECT 0.000 16.416 0.024 16.440 ;
    END
  END w_mask_in[21]
  PIN w_mask_in[22]
    DIRECTION INPUT ;
    USE SIGNAL ;
    SHAPE ABUTMENT ;
    PORT
      LAYER M4 ;
      RECT 0.000 16.512 0.024 16.536 ;
    END
  END w_mask_in[22]
  PIN w_mask_in[23]
    DIRECTION INPUT ;
    USE SIGNAL ;
    SHAPE ABUTMENT ;
    PORT
      LAYER M4 ;
      RECT 0.000 16.608 0.024 16.632 ;
    END
  END w_mask_in[23]
  PIN w_mask_in[24]
    DIRECTION INPUT ;
    USE SIGNAL ;
    SHAPE ABUTMENT ;
    PORT
      LAYER M4 ;
      RECT 0.000 16.704 0.024 16.728 ;
    END
  END w_mask_in[24]
  PIN w_mask_in[25]
    DIRECTION INPUT ;
    USE SIGNAL ;
    SHAPE ABUTMENT ;
    PORT
      LAYER M4 ;
      RECT 0.000 16.800 0.024 16.824 ;
    END
  END w_mask_in[25]
  PIN w_mask_in[26]
    DIRECTION INPUT ;
    USE SIGNAL ;
    SHAPE ABUTMENT ;
    PORT
      LAYER M4 ;
      RECT 0.000 16.896 0.024 16.920 ;
    END
  END w_mask_in[26]
  PIN w_mask_in[27]
    DIRECTION INPUT ;
    USE SIGNAL ;
    SHAPE ABUTMENT ;
    PORT
      LAYER M4 ;
      RECT 0.000 16.992 0.024 17.016 ;
    END
  END w_mask_in[27]
  PIN w_mask_in[28]
    DIRECTION INPUT ;
    USE SIGNAL ;
    SHAPE ABUTMENT ;
    PORT
      LAYER M4 ;
      RECT 0.000 17.088 0.024 17.112 ;
    END
  END w_mask_in[28]
  PIN w_mask_in[29]
    DIRECTION INPUT ;
    USE SIGNAL ;
    SHAPE ABUTMENT ;
    PORT
      LAYER M4 ;
      RECT 0.000 17.184 0.024 17.208 ;
    END
  END w_mask_in[29]
  PIN w_mask_in[30]
    DIRECTION INPUT ;
    USE SIGNAL ;
    SHAPE ABUTMENT ;
    PORT
      LAYER M4 ;
      RECT 0.000 17.280 0.024 17.304 ;
    END
  END w_mask_in[30]
  PIN w_mask_in[31]
    DIRECTION INPUT ;
    USE SIGNAL ;
    SHAPE ABUTMENT ;
    PORT
      LAYER M4 ;
      RECT 0.000 17.376 0.024 17.400 ;
    END
  END w_mask_in[31]
  PIN w_mask_in[32]
    DIRECTION INPUT ;
    USE SIGNAL ;
    SHAPE ABUTMENT ;
    PORT
      LAYER M4 ;
      RECT 0.000 17.472 0.024 17.496 ;
    END
  END w_mask_in[32]
  PIN w_mask_in[33]
    DIRECTION INPUT ;
    USE SIGNAL ;
    SHAPE ABUTMENT ;
    PORT
      LAYER M4 ;
      RECT 0.000 17.568 0.024 17.592 ;
    END
  END w_mask_in[33]
  PIN w_mask_in[34]
    DIRECTION INPUT ;
    USE SIGNAL ;
    SHAPE ABUTMENT ;
    PORT
      LAYER M4 ;
      RECT 0.000 17.664 0.024 17.688 ;
    END
  END w_mask_in[34]
  PIN w_mask_in[35]
    DIRECTION INPUT ;
    USE SIGNAL ;
    SHAPE ABUTMENT ;
    PORT
      LAYER M4 ;
      RECT 0.000 17.760 0.024 17.784 ;
    END
  END w_mask_in[35]
  PIN w_mask_in[36]
    DIRECTION INPUT ;
    USE SIGNAL ;
    SHAPE ABUTMENT ;
    PORT
      LAYER M4 ;
      RECT 0.000 17.856 0.024 17.880 ;
    END
  END w_mask_in[36]
  PIN w_mask_in[37]
    DIRECTION INPUT ;
    USE SIGNAL ;
    SHAPE ABUTMENT ;
    PORT
      LAYER M4 ;
      RECT 0.000 17.952 0.024 17.976 ;
    END
  END w_mask_in[37]
  PIN w_mask_in[38]
    DIRECTION INPUT ;
    USE SIGNAL ;
    SHAPE ABUTMENT ;
    PORT
      LAYER M4 ;
      RECT 0.000 18.048 0.024 18.072 ;
    END
  END w_mask_in[38]
  PIN w_mask_in[39]
    DIRECTION INPUT ;
    USE SIGNAL ;
    SHAPE ABUTMENT ;
    PORT
      LAYER M4 ;
      RECT 0.000 18.144 0.024 18.168 ;
    END
  END w_mask_in[39]
  PIN w_mask_in[40]
    DIRECTION INPUT ;
    USE SIGNAL ;
    SHAPE ABUTMENT ;
    PORT
      LAYER M4 ;
      RECT 0.000 18.240 0.024 18.264 ;
    END
  END w_mask_in[40]
  PIN w_mask_in[41]
    DIRECTION INPUT ;
    USE SIGNAL ;
    SHAPE ABUTMENT ;
    PORT
      LAYER M4 ;
      RECT 0.000 18.336 0.024 18.360 ;
    END
  END w_mask_in[41]
  PIN w_mask_in[42]
    DIRECTION INPUT ;
    USE SIGNAL ;
    SHAPE ABUTMENT ;
    PORT
      LAYER M4 ;
      RECT 0.000 18.432 0.024 18.456 ;
    END
  END w_mask_in[42]
  PIN w_mask_in[43]
    DIRECTION INPUT ;
    USE SIGNAL ;
    SHAPE ABUTMENT ;
    PORT
      LAYER M4 ;
      RECT 0.000 18.528 0.024 18.552 ;
    END
  END w_mask_in[43]
  PIN w_mask_in[44]
    DIRECTION INPUT ;
    USE SIGNAL ;
    SHAPE ABUTMENT ;
    PORT
      LAYER M4 ;
      RECT 0.000 18.624 0.024 18.648 ;
    END
  END w_mask_in[44]
  PIN w_mask_in[45]
    DIRECTION INPUT ;
    USE SIGNAL ;
    SHAPE ABUTMENT ;
    PORT
      LAYER M4 ;
      RECT 0.000 18.720 0.024 18.744 ;
    END
  END w_mask_in[45]
  PIN w_mask_in[46]
    DIRECTION INPUT ;
    USE SIGNAL ;
    SHAPE ABUTMENT ;
    PORT
      LAYER M4 ;
      RECT 0.000 18.816 0.024 18.840 ;
    END
  END w_mask_in[46]
  PIN w_mask_in[47]
    DIRECTION INPUT ;
    USE SIGNAL ;
    SHAPE ABUTMENT ;
    PORT
      LAYER M4 ;
      RECT 0.000 18.912 0.024 18.936 ;
    END
  END w_mask_in[47]
  PIN w_mask_in[48]
    DIRECTION INPUT ;
    USE SIGNAL ;
    SHAPE ABUTMENT ;
    PORT
      LAYER M4 ;
      RECT 0.000 19.008 0.024 19.032 ;
    END
  END w_mask_in[48]
  PIN w_mask_in[49]
    DIRECTION INPUT ;
    USE SIGNAL ;
    SHAPE ABUTMENT ;
    PORT
      LAYER M4 ;
      RECT 0.000 19.104 0.024 19.128 ;
    END
  END w_mask_in[49]
  PIN w_mask_in[50]
    DIRECTION INPUT ;
    USE SIGNAL ;
    SHAPE ABUTMENT ;
    PORT
      LAYER M4 ;
      RECT 0.000 19.200 0.024 19.224 ;
    END
  END w_mask_in[50]
  PIN w_mask_in[51]
    DIRECTION INPUT ;
    USE SIGNAL ;
    SHAPE ABUTMENT ;
    PORT
      LAYER M4 ;
      RECT 0.000 19.296 0.024 19.320 ;
    END
  END w_mask_in[51]
  PIN w_mask_in[52]
    DIRECTION INPUT ;
    USE SIGNAL ;
    SHAPE ABUTMENT ;
    PORT
      LAYER M4 ;
      RECT 0.000 19.392 0.024 19.416 ;
    END
  END w_mask_in[52]
  PIN w_mask_in[53]
    DIRECTION INPUT ;
    USE SIGNAL ;
    SHAPE ABUTMENT ;
    PORT
      LAYER M4 ;
      RECT 0.000 19.488 0.024 19.512 ;
    END
  END w_mask_in[53]
  PIN w_mask_in[54]
    DIRECTION INPUT ;
    USE SIGNAL ;
    SHAPE ABUTMENT ;
    PORT
      LAYER M4 ;
      RECT 0.000 19.584 0.024 19.608 ;
    END
  END w_mask_in[54]
  PIN w_mask_in[55]
    DIRECTION INPUT ;
    USE SIGNAL ;
    SHAPE ABUTMENT ;
    PORT
      LAYER M4 ;
      RECT 0.000 19.680 0.024 19.704 ;
    END
  END w_mask_in[55]
  PIN w_mask_in[56]
    DIRECTION INPUT ;
    USE SIGNAL ;
    SHAPE ABUTMENT ;
    PORT
      LAYER M4 ;
      RECT 0.000 19.776 0.024 19.800 ;
    END
  END w_mask_in[56]
  PIN w_mask_in[57]
    DIRECTION INPUT ;
    USE SIGNAL ;
    SHAPE ABUTMENT ;
    PORT
      LAYER M4 ;
      RECT 118.776 0.768 118.800 0.792 ;
    END
  END w_mask_in[57]
  PIN w_mask_in[58]
    DIRECTION INPUT ;
    USE SIGNAL ;
    SHAPE ABUTMENT ;
    PORT
      LAYER M4 ;
      RECT 118.776 0.864 118.800 0.888 ;
    END
  END w_mask_in[58]
  PIN w_mask_in[59]
    DIRECTION INPUT ;
    USE SIGNAL ;
    SHAPE ABUTMENT ;
    PORT
      LAYER M4 ;
      RECT 118.776 0.960 118.800 0.984 ;
    END
  END w_mask_in[59]
  PIN w_mask_in[60]
    DIRECTION INPUT ;
    USE SIGNAL ;
    SHAPE ABUTMENT ;
    PORT
      LAYER M4 ;
      RECT 118.776 1.056 118.800 1.080 ;
    END
  END w_mask_in[60]
  PIN w_mask_in[61]
    DIRECTION INPUT ;
    USE SIGNAL ;
    SHAPE ABUTMENT ;
    PORT
      LAYER M4 ;
      RECT 118.776 1.152 118.800 1.176 ;
    END
  END w_mask_in[61]
  PIN w_mask_in[62]
    DIRECTION INPUT ;
    USE SIGNAL ;
    SHAPE ABUTMENT ;
    PORT
      LAYER M4 ;
      RECT 118.776 1.248 118.800 1.272 ;
    END
  END w_mask_in[62]
  PIN w_mask_in[63]
    DIRECTION INPUT ;
    USE SIGNAL ;
    SHAPE ABUTMENT ;
    PORT
      LAYER M4 ;
      RECT 118.776 1.344 118.800 1.368 ;
    END
  END w_mask_in[63]
  PIN w_mask_in[64]
    DIRECTION INPUT ;
    USE SIGNAL ;
    SHAPE ABUTMENT ;
    PORT
      LAYER M4 ;
      RECT 118.776 1.440 118.800 1.464 ;
    END
  END w_mask_in[64]
  PIN w_mask_in[65]
    DIRECTION INPUT ;
    USE SIGNAL ;
    SHAPE ABUTMENT ;
    PORT
      LAYER M4 ;
      RECT 118.776 1.536 118.800 1.560 ;
    END
  END w_mask_in[65]
  PIN w_mask_in[66]
    DIRECTION INPUT ;
    USE SIGNAL ;
    SHAPE ABUTMENT ;
    PORT
      LAYER M4 ;
      RECT 118.776 1.632 118.800 1.656 ;
    END
  END w_mask_in[66]
  PIN w_mask_in[67]
    DIRECTION INPUT ;
    USE SIGNAL ;
    SHAPE ABUTMENT ;
    PORT
      LAYER M4 ;
      RECT 118.776 1.728 118.800 1.752 ;
    END
  END w_mask_in[67]
  PIN w_mask_in[68]
    DIRECTION INPUT ;
    USE SIGNAL ;
    SHAPE ABUTMENT ;
    PORT
      LAYER M4 ;
      RECT 118.776 1.824 118.800 1.848 ;
    END
  END w_mask_in[68]
  PIN w_mask_in[69]
    DIRECTION INPUT ;
    USE SIGNAL ;
    SHAPE ABUTMENT ;
    PORT
      LAYER M4 ;
      RECT 118.776 1.920 118.800 1.944 ;
    END
  END w_mask_in[69]
  PIN w_mask_in[70]
    DIRECTION INPUT ;
    USE SIGNAL ;
    SHAPE ABUTMENT ;
    PORT
      LAYER M4 ;
      RECT 118.776 2.016 118.800 2.040 ;
    END
  END w_mask_in[70]
  PIN w_mask_in[71]
    DIRECTION INPUT ;
    USE SIGNAL ;
    SHAPE ABUTMENT ;
    PORT
      LAYER M4 ;
      RECT 118.776 2.112 118.800 2.136 ;
    END
  END w_mask_in[71]
  PIN w_mask_in[72]
    DIRECTION INPUT ;
    USE SIGNAL ;
    SHAPE ABUTMENT ;
    PORT
      LAYER M4 ;
      RECT 118.776 2.208 118.800 2.232 ;
    END
  END w_mask_in[72]
  PIN w_mask_in[73]
    DIRECTION INPUT ;
    USE SIGNAL ;
    SHAPE ABUTMENT ;
    PORT
      LAYER M4 ;
      RECT 118.776 2.304 118.800 2.328 ;
    END
  END w_mask_in[73]
  PIN w_mask_in[74]
    DIRECTION INPUT ;
    USE SIGNAL ;
    SHAPE ABUTMENT ;
    PORT
      LAYER M4 ;
      RECT 118.776 2.400 118.800 2.424 ;
    END
  END w_mask_in[74]
  PIN w_mask_in[75]
    DIRECTION INPUT ;
    USE SIGNAL ;
    SHAPE ABUTMENT ;
    PORT
      LAYER M4 ;
      RECT 118.776 2.496 118.800 2.520 ;
    END
  END w_mask_in[75]
  PIN w_mask_in[76]
    DIRECTION INPUT ;
    USE SIGNAL ;
    SHAPE ABUTMENT ;
    PORT
      LAYER M4 ;
      RECT 118.776 2.592 118.800 2.616 ;
    END
  END w_mask_in[76]
  PIN w_mask_in[77]
    DIRECTION INPUT ;
    USE SIGNAL ;
    SHAPE ABUTMENT ;
    PORT
      LAYER M4 ;
      RECT 118.776 2.688 118.800 2.712 ;
    END
  END w_mask_in[77]
  PIN w_mask_in[78]
    DIRECTION INPUT ;
    USE SIGNAL ;
    SHAPE ABUTMENT ;
    PORT
      LAYER M4 ;
      RECT 118.776 2.784 118.800 2.808 ;
    END
  END w_mask_in[78]
  PIN w_mask_in[79]
    DIRECTION INPUT ;
    USE SIGNAL ;
    SHAPE ABUTMENT ;
    PORT
      LAYER M4 ;
      RECT 118.776 2.880 118.800 2.904 ;
    END
  END w_mask_in[79]
  PIN w_mask_in[80]
    DIRECTION INPUT ;
    USE SIGNAL ;
    SHAPE ABUTMENT ;
    PORT
      LAYER M4 ;
      RECT 118.776 2.976 118.800 3.000 ;
    END
  END w_mask_in[80]
  PIN w_mask_in[81]
    DIRECTION INPUT ;
    USE SIGNAL ;
    SHAPE ABUTMENT ;
    PORT
      LAYER M4 ;
      RECT 118.776 3.072 118.800 3.096 ;
    END
  END w_mask_in[81]
  PIN w_mask_in[82]
    DIRECTION INPUT ;
    USE SIGNAL ;
    SHAPE ABUTMENT ;
    PORT
      LAYER M4 ;
      RECT 118.776 3.168 118.800 3.192 ;
    END
  END w_mask_in[82]
  PIN w_mask_in[83]
    DIRECTION INPUT ;
    USE SIGNAL ;
    SHAPE ABUTMENT ;
    PORT
      LAYER M4 ;
      RECT 118.776 3.264 118.800 3.288 ;
    END
  END w_mask_in[83]
  PIN w_mask_in[84]
    DIRECTION INPUT ;
    USE SIGNAL ;
    SHAPE ABUTMENT ;
    PORT
      LAYER M4 ;
      RECT 118.776 3.360 118.800 3.384 ;
    END
  END w_mask_in[84]
  PIN w_mask_in[85]
    DIRECTION INPUT ;
    USE SIGNAL ;
    SHAPE ABUTMENT ;
    PORT
      LAYER M4 ;
      RECT 118.776 3.456 118.800 3.480 ;
    END
  END w_mask_in[85]
  PIN w_mask_in[86]
    DIRECTION INPUT ;
    USE SIGNAL ;
    SHAPE ABUTMENT ;
    PORT
      LAYER M4 ;
      RECT 118.776 3.552 118.800 3.576 ;
    END
  END w_mask_in[86]
  PIN w_mask_in[87]
    DIRECTION INPUT ;
    USE SIGNAL ;
    SHAPE ABUTMENT ;
    PORT
      LAYER M4 ;
      RECT 118.776 3.648 118.800 3.672 ;
    END
  END w_mask_in[87]
  PIN w_mask_in[88]
    DIRECTION INPUT ;
    USE SIGNAL ;
    SHAPE ABUTMENT ;
    PORT
      LAYER M4 ;
      RECT 118.776 3.744 118.800 3.768 ;
    END
  END w_mask_in[88]
  PIN w_mask_in[89]
    DIRECTION INPUT ;
    USE SIGNAL ;
    SHAPE ABUTMENT ;
    PORT
      LAYER M4 ;
      RECT 118.776 3.840 118.800 3.864 ;
    END
  END w_mask_in[89]
  PIN w_mask_in[90]
    DIRECTION INPUT ;
    USE SIGNAL ;
    SHAPE ABUTMENT ;
    PORT
      LAYER M4 ;
      RECT 118.776 3.936 118.800 3.960 ;
    END
  END w_mask_in[90]
  PIN w_mask_in[91]
    DIRECTION INPUT ;
    USE SIGNAL ;
    SHAPE ABUTMENT ;
    PORT
      LAYER M4 ;
      RECT 118.776 4.032 118.800 4.056 ;
    END
  END w_mask_in[91]
  PIN w_mask_in[92]
    DIRECTION INPUT ;
    USE SIGNAL ;
    SHAPE ABUTMENT ;
    PORT
      LAYER M4 ;
      RECT 118.776 4.128 118.800 4.152 ;
    END
  END w_mask_in[92]
  PIN w_mask_in[93]
    DIRECTION INPUT ;
    USE SIGNAL ;
    SHAPE ABUTMENT ;
    PORT
      LAYER M4 ;
      RECT 118.776 4.224 118.800 4.248 ;
    END
  END w_mask_in[93]
  PIN w_mask_in[94]
    DIRECTION INPUT ;
    USE SIGNAL ;
    SHAPE ABUTMENT ;
    PORT
      LAYER M4 ;
      RECT 118.776 4.320 118.800 4.344 ;
    END
  END w_mask_in[94]
  PIN w_mask_in[95]
    DIRECTION INPUT ;
    USE SIGNAL ;
    SHAPE ABUTMENT ;
    PORT
      LAYER M4 ;
      RECT 118.776 4.416 118.800 4.440 ;
    END
  END w_mask_in[95]
  PIN w_mask_in[96]
    DIRECTION INPUT ;
    USE SIGNAL ;
    SHAPE ABUTMENT ;
    PORT
      LAYER M4 ;
      RECT 118.776 4.512 118.800 4.536 ;
    END
  END w_mask_in[96]
  PIN w_mask_in[97]
    DIRECTION INPUT ;
    USE SIGNAL ;
    SHAPE ABUTMENT ;
    PORT
      LAYER M4 ;
      RECT 118.776 4.608 118.800 4.632 ;
    END
  END w_mask_in[97]
  PIN w_mask_in[98]
    DIRECTION INPUT ;
    USE SIGNAL ;
    SHAPE ABUTMENT ;
    PORT
      LAYER M4 ;
      RECT 118.776 4.704 118.800 4.728 ;
    END
  END w_mask_in[98]
  PIN w_mask_in[99]
    DIRECTION INPUT ;
    USE SIGNAL ;
    SHAPE ABUTMENT ;
    PORT
      LAYER M4 ;
      RECT 118.776 4.800 118.800 4.824 ;
    END
  END w_mask_in[99]
  PIN w_mask_in[100]
    DIRECTION INPUT ;
    USE SIGNAL ;
    SHAPE ABUTMENT ;
    PORT
      LAYER M4 ;
      RECT 118.776 4.896 118.800 4.920 ;
    END
  END w_mask_in[100]
  PIN w_mask_in[101]
    DIRECTION INPUT ;
    USE SIGNAL ;
    SHAPE ABUTMENT ;
    PORT
      LAYER M4 ;
      RECT 118.776 4.992 118.800 5.016 ;
    END
  END w_mask_in[101]
  PIN w_mask_in[102]
    DIRECTION INPUT ;
    USE SIGNAL ;
    SHAPE ABUTMENT ;
    PORT
      LAYER M4 ;
      RECT 118.776 5.088 118.800 5.112 ;
    END
  END w_mask_in[102]
  PIN w_mask_in[103]
    DIRECTION INPUT ;
    USE SIGNAL ;
    SHAPE ABUTMENT ;
    PORT
      LAYER M4 ;
      RECT 118.776 5.184 118.800 5.208 ;
    END
  END w_mask_in[103]
  PIN w_mask_in[104]
    DIRECTION INPUT ;
    USE SIGNAL ;
    SHAPE ABUTMENT ;
    PORT
      LAYER M4 ;
      RECT 118.776 5.280 118.800 5.304 ;
    END
  END w_mask_in[104]
  PIN w_mask_in[105]
    DIRECTION INPUT ;
    USE SIGNAL ;
    SHAPE ABUTMENT ;
    PORT
      LAYER M4 ;
      RECT 118.776 5.376 118.800 5.400 ;
    END
  END w_mask_in[105]
  PIN w_mask_in[106]
    DIRECTION INPUT ;
    USE SIGNAL ;
    SHAPE ABUTMENT ;
    PORT
      LAYER M4 ;
      RECT 118.776 5.472 118.800 5.496 ;
    END
  END w_mask_in[106]
  PIN w_mask_in[107]
    DIRECTION INPUT ;
    USE SIGNAL ;
    SHAPE ABUTMENT ;
    PORT
      LAYER M4 ;
      RECT 118.776 5.568 118.800 5.592 ;
    END
  END w_mask_in[107]
  PIN w_mask_in[108]
    DIRECTION INPUT ;
    USE SIGNAL ;
    SHAPE ABUTMENT ;
    PORT
      LAYER M4 ;
      RECT 118.776 5.664 118.800 5.688 ;
    END
  END w_mask_in[108]
  PIN w_mask_in[109]
    DIRECTION INPUT ;
    USE SIGNAL ;
    SHAPE ABUTMENT ;
    PORT
      LAYER M4 ;
      RECT 118.776 5.760 118.800 5.784 ;
    END
  END w_mask_in[109]
  PIN w_mask_in[110]
    DIRECTION INPUT ;
    USE SIGNAL ;
    SHAPE ABUTMENT ;
    PORT
      LAYER M4 ;
      RECT 118.776 5.856 118.800 5.880 ;
    END
  END w_mask_in[110]
  PIN w_mask_in[111]
    DIRECTION INPUT ;
    USE SIGNAL ;
    SHAPE ABUTMENT ;
    PORT
      LAYER M4 ;
      RECT 118.776 5.952 118.800 5.976 ;
    END
  END w_mask_in[111]
  PIN w_mask_in[112]
    DIRECTION INPUT ;
    USE SIGNAL ;
    SHAPE ABUTMENT ;
    PORT
      LAYER M4 ;
      RECT 118.776 6.048 118.800 6.072 ;
    END
  END w_mask_in[112]
  PIN w_mask_in[113]
    DIRECTION INPUT ;
    USE SIGNAL ;
    SHAPE ABUTMENT ;
    PORT
      LAYER M4 ;
      RECT 118.776 6.144 118.800 6.168 ;
    END
  END w_mask_in[113]
  PIN w_mask_in[114]
    DIRECTION INPUT ;
    USE SIGNAL ;
    SHAPE ABUTMENT ;
    PORT
      LAYER M4 ;
      RECT 118.776 6.240 118.800 6.264 ;
    END
  END w_mask_in[114]
  PIN w_mask_in[115]
    DIRECTION INPUT ;
    USE SIGNAL ;
    SHAPE ABUTMENT ;
    PORT
      LAYER M4 ;
      RECT 118.776 6.336 118.800 6.360 ;
    END
  END w_mask_in[115]
  PIN w_mask_in[116]
    DIRECTION INPUT ;
    USE SIGNAL ;
    SHAPE ABUTMENT ;
    PORT
      LAYER M4 ;
      RECT 118.776 6.432 118.800 6.456 ;
    END
  END w_mask_in[116]
  PIN w_mask_in[117]
    DIRECTION INPUT ;
    USE SIGNAL ;
    SHAPE ABUTMENT ;
    PORT
      LAYER M4 ;
      RECT 118.776 6.528 118.800 6.552 ;
    END
  END w_mask_in[117]
  PIN w_mask_in[118]
    DIRECTION INPUT ;
    USE SIGNAL ;
    SHAPE ABUTMENT ;
    PORT
      LAYER M4 ;
      RECT 118.776 6.624 118.800 6.648 ;
    END
  END w_mask_in[118]
  PIN w_mask_in[119]
    DIRECTION INPUT ;
    USE SIGNAL ;
    SHAPE ABUTMENT ;
    PORT
      LAYER M4 ;
      RECT 118.776 6.720 118.800 6.744 ;
    END
  END w_mask_in[119]
  PIN w_mask_in[120]
    DIRECTION INPUT ;
    USE SIGNAL ;
    SHAPE ABUTMENT ;
    PORT
      LAYER M4 ;
      RECT 118.776 6.816 118.800 6.840 ;
    END
  END w_mask_in[120]
  PIN w_mask_in[121]
    DIRECTION INPUT ;
    USE SIGNAL ;
    SHAPE ABUTMENT ;
    PORT
      LAYER M4 ;
      RECT 118.776 6.912 118.800 6.936 ;
    END
  END w_mask_in[121]
  PIN w_mask_in[122]
    DIRECTION INPUT ;
    USE SIGNAL ;
    SHAPE ABUTMENT ;
    PORT
      LAYER M4 ;
      RECT 118.776 7.008 118.800 7.032 ;
    END
  END w_mask_in[122]
  PIN w_mask_in[123]
    DIRECTION INPUT ;
    USE SIGNAL ;
    SHAPE ABUTMENT ;
    PORT
      LAYER M4 ;
      RECT 118.776 7.104 118.800 7.128 ;
    END
  END w_mask_in[123]
  PIN w_mask_in[124]
    DIRECTION INPUT ;
    USE SIGNAL ;
    SHAPE ABUTMENT ;
    PORT
      LAYER M4 ;
      RECT 118.776 7.200 118.800 7.224 ;
    END
  END w_mask_in[124]
  PIN w_mask_in[125]
    DIRECTION INPUT ;
    USE SIGNAL ;
    SHAPE ABUTMENT ;
    PORT
      LAYER M4 ;
      RECT 118.776 7.296 118.800 7.320 ;
    END
  END w_mask_in[125]
  PIN w_mask_in[126]
    DIRECTION INPUT ;
    USE SIGNAL ;
    SHAPE ABUTMENT ;
    PORT
      LAYER M4 ;
      RECT 118.776 7.392 118.800 7.416 ;
    END
  END w_mask_in[126]
  PIN w_mask_in[127]
    DIRECTION INPUT ;
    USE SIGNAL ;
    SHAPE ABUTMENT ;
    PORT
      LAYER M4 ;
      RECT 118.776 7.488 118.800 7.512 ;
    END
  END w_mask_in[127]
  PIN rd_out[0]
    DIRECTION OUTPUT ;
    USE SIGNAL ;
    SHAPE ABUTMENT ;
    PORT
      LAYER M4 ;
      RECT 118.776 7.584 118.800 7.608 ;
    END
  END rd_out[0]
  PIN rd_out[1]
    DIRECTION OUTPUT ;
    USE SIGNAL ;
    SHAPE ABUTMENT ;
    PORT
      LAYER M4 ;
      RECT 118.776 7.680 118.800 7.704 ;
    END
  END rd_out[1]
  PIN rd_out[2]
    DIRECTION OUTPUT ;
    USE SIGNAL ;
    SHAPE ABUTMENT ;
    PORT
      LAYER M4 ;
      RECT 118.776 7.776 118.800 7.800 ;
    END
  END rd_out[2]
  PIN rd_out[3]
    DIRECTION OUTPUT ;
    USE SIGNAL ;
    SHAPE ABUTMENT ;
    PORT
      LAYER M4 ;
      RECT 118.776 7.872 118.800 7.896 ;
    END
  END rd_out[3]
  PIN rd_out[4]
    DIRECTION OUTPUT ;
    USE SIGNAL ;
    SHAPE ABUTMENT ;
    PORT
      LAYER M4 ;
      RECT 118.776 7.968 118.800 7.992 ;
    END
  END rd_out[4]
  PIN rd_out[5]
    DIRECTION OUTPUT ;
    USE SIGNAL ;
    SHAPE ABUTMENT ;
    PORT
      LAYER M4 ;
      RECT 118.776 8.064 118.800 8.088 ;
    END
  END rd_out[5]
  PIN rd_out[6]
    DIRECTION OUTPUT ;
    USE SIGNAL ;
    SHAPE ABUTMENT ;
    PORT
      LAYER M4 ;
      RECT 118.776 8.160 118.800 8.184 ;
    END
  END rd_out[6]
  PIN rd_out[7]
    DIRECTION OUTPUT ;
    USE SIGNAL ;
    SHAPE ABUTMENT ;
    PORT
      LAYER M4 ;
      RECT 118.776 8.256 118.800 8.280 ;
    END
  END rd_out[7]
  PIN rd_out[8]
    DIRECTION OUTPUT ;
    USE SIGNAL ;
    SHAPE ABUTMENT ;
    PORT
      LAYER M4 ;
      RECT 118.776 8.352 118.800 8.376 ;
    END
  END rd_out[8]
  PIN rd_out[9]
    DIRECTION OUTPUT ;
    USE SIGNAL ;
    SHAPE ABUTMENT ;
    PORT
      LAYER M4 ;
      RECT 118.776 8.448 118.800 8.472 ;
    END
  END rd_out[9]
  PIN rd_out[10]
    DIRECTION OUTPUT ;
    USE SIGNAL ;
    SHAPE ABUTMENT ;
    PORT
      LAYER M4 ;
      RECT 118.776 8.544 118.800 8.568 ;
    END
  END rd_out[10]
  PIN rd_out[11]
    DIRECTION OUTPUT ;
    USE SIGNAL ;
    SHAPE ABUTMENT ;
    PORT
      LAYER M4 ;
      RECT 118.776 8.640 118.800 8.664 ;
    END
  END rd_out[11]
  PIN rd_out[12]
    DIRECTION OUTPUT ;
    USE SIGNAL ;
    SHAPE ABUTMENT ;
    PORT
      LAYER M4 ;
      RECT 118.776 8.736 118.800 8.760 ;
    END
  END rd_out[12]
  PIN rd_out[13]
    DIRECTION OUTPUT ;
    USE SIGNAL ;
    SHAPE ABUTMENT ;
    PORT
      LAYER M4 ;
      RECT 118.776 8.832 118.800 8.856 ;
    END
  END rd_out[13]
  PIN rd_out[14]
    DIRECTION OUTPUT ;
    USE SIGNAL ;
    SHAPE ABUTMENT ;
    PORT
      LAYER M4 ;
      RECT 118.776 8.928 118.800 8.952 ;
    END
  END rd_out[14]
  PIN rd_out[15]
    DIRECTION OUTPUT ;
    USE SIGNAL ;
    SHAPE ABUTMENT ;
    PORT
      LAYER M4 ;
      RECT 118.776 9.024 118.800 9.048 ;
    END
  END rd_out[15]
  PIN rd_out[16]
    DIRECTION OUTPUT ;
    USE SIGNAL ;
    SHAPE ABUTMENT ;
    PORT
      LAYER M4 ;
      RECT 118.776 9.120 118.800 9.144 ;
    END
  END rd_out[16]
  PIN rd_out[17]
    DIRECTION OUTPUT ;
    USE SIGNAL ;
    SHAPE ABUTMENT ;
    PORT
      LAYER M4 ;
      RECT 118.776 9.216 118.800 9.240 ;
    END
  END rd_out[17]
  PIN rd_out[18]
    DIRECTION OUTPUT ;
    USE SIGNAL ;
    SHAPE ABUTMENT ;
    PORT
      LAYER M4 ;
      RECT 118.776 9.312 118.800 9.336 ;
    END
  END rd_out[18]
  PIN rd_out[19]
    DIRECTION OUTPUT ;
    USE SIGNAL ;
    SHAPE ABUTMENT ;
    PORT
      LAYER M4 ;
      RECT 118.776 9.408 118.800 9.432 ;
    END
  END rd_out[19]
  PIN rd_out[20]
    DIRECTION OUTPUT ;
    USE SIGNAL ;
    SHAPE ABUTMENT ;
    PORT
      LAYER M4 ;
      RECT 118.776 9.504 118.800 9.528 ;
    END
  END rd_out[20]
  PIN rd_out[21]
    DIRECTION OUTPUT ;
    USE SIGNAL ;
    SHAPE ABUTMENT ;
    PORT
      LAYER M4 ;
      RECT 118.776 9.600 118.800 9.624 ;
    END
  END rd_out[21]
  PIN rd_out[22]
    DIRECTION OUTPUT ;
    USE SIGNAL ;
    SHAPE ABUTMENT ;
    PORT
      LAYER M4 ;
      RECT 118.776 9.696 118.800 9.720 ;
    END
  END rd_out[22]
  PIN rd_out[23]
    DIRECTION OUTPUT ;
    USE SIGNAL ;
    SHAPE ABUTMENT ;
    PORT
      LAYER M4 ;
      RECT 118.776 9.792 118.800 9.816 ;
    END
  END rd_out[23]
  PIN rd_out[24]
    DIRECTION OUTPUT ;
    USE SIGNAL ;
    SHAPE ABUTMENT ;
    PORT
      LAYER M4 ;
      RECT 118.776 9.888 118.800 9.912 ;
    END
  END rd_out[24]
  PIN rd_out[25]
    DIRECTION OUTPUT ;
    USE SIGNAL ;
    SHAPE ABUTMENT ;
    PORT
      LAYER M4 ;
      RECT 118.776 9.984 118.800 10.008 ;
    END
  END rd_out[25]
  PIN rd_out[26]
    DIRECTION OUTPUT ;
    USE SIGNAL ;
    SHAPE ABUTMENT ;
    PORT
      LAYER M4 ;
      RECT 118.776 10.080 118.800 10.104 ;
    END
  END rd_out[26]
  PIN rd_out[27]
    DIRECTION OUTPUT ;
    USE SIGNAL ;
    SHAPE ABUTMENT ;
    PORT
      LAYER M4 ;
      RECT 118.776 10.176 118.800 10.200 ;
    END
  END rd_out[27]
  PIN rd_out[28]
    DIRECTION OUTPUT ;
    USE SIGNAL ;
    SHAPE ABUTMENT ;
    PORT
      LAYER M4 ;
      RECT 118.776 10.272 118.800 10.296 ;
    END
  END rd_out[28]
  PIN rd_out[29]
    DIRECTION OUTPUT ;
    USE SIGNAL ;
    SHAPE ABUTMENT ;
    PORT
      LAYER M4 ;
      RECT 118.776 10.368 118.800 10.392 ;
    END
  END rd_out[29]
  PIN rd_out[30]
    DIRECTION OUTPUT ;
    USE SIGNAL ;
    SHAPE ABUTMENT ;
    PORT
      LAYER M4 ;
      RECT 118.776 10.464 118.800 10.488 ;
    END
  END rd_out[30]
  PIN rd_out[31]
    DIRECTION OUTPUT ;
    USE SIGNAL ;
    SHAPE ABUTMENT ;
    PORT
      LAYER M4 ;
      RECT 118.776 10.560 118.800 10.584 ;
    END
  END rd_out[31]
  PIN rd_out[32]
    DIRECTION OUTPUT ;
    USE SIGNAL ;
    SHAPE ABUTMENT ;
    PORT
      LAYER M4 ;
      RECT 118.776 10.656 118.800 10.680 ;
    END
  END rd_out[32]
  PIN rd_out[33]
    DIRECTION OUTPUT ;
    USE SIGNAL ;
    SHAPE ABUTMENT ;
    PORT
      LAYER M4 ;
      RECT 118.776 10.752 118.800 10.776 ;
    END
  END rd_out[33]
  PIN rd_out[34]
    DIRECTION OUTPUT ;
    USE SIGNAL ;
    SHAPE ABUTMENT ;
    PORT
      LAYER M4 ;
      RECT 118.776 10.848 118.800 10.872 ;
    END
  END rd_out[34]
  PIN rd_out[35]
    DIRECTION OUTPUT ;
    USE SIGNAL ;
    SHAPE ABUTMENT ;
    PORT
      LAYER M4 ;
      RECT 118.776 10.944 118.800 10.968 ;
    END
  END rd_out[35]
  PIN rd_out[36]
    DIRECTION OUTPUT ;
    USE SIGNAL ;
    SHAPE ABUTMENT ;
    PORT
      LAYER M4 ;
      RECT 118.776 11.040 118.800 11.064 ;
    END
  END rd_out[36]
  PIN rd_out[37]
    DIRECTION OUTPUT ;
    USE SIGNAL ;
    SHAPE ABUTMENT ;
    PORT
      LAYER M4 ;
      RECT 118.776 11.136 118.800 11.160 ;
    END
  END rd_out[37]
  PIN rd_out[38]
    DIRECTION OUTPUT ;
    USE SIGNAL ;
    SHAPE ABUTMENT ;
    PORT
      LAYER M4 ;
      RECT 118.776 11.232 118.800 11.256 ;
    END
  END rd_out[38]
  PIN rd_out[39]
    DIRECTION OUTPUT ;
    USE SIGNAL ;
    SHAPE ABUTMENT ;
    PORT
      LAYER M4 ;
      RECT 118.776 11.328 118.800 11.352 ;
    END
  END rd_out[39]
  PIN rd_out[40]
    DIRECTION OUTPUT ;
    USE SIGNAL ;
    SHAPE ABUTMENT ;
    PORT
      LAYER M4 ;
      RECT 118.776 11.424 118.800 11.448 ;
    END
  END rd_out[40]
  PIN rd_out[41]
    DIRECTION OUTPUT ;
    USE SIGNAL ;
    SHAPE ABUTMENT ;
    PORT
      LAYER M4 ;
      RECT 118.776 11.520 118.800 11.544 ;
    END
  END rd_out[41]
  PIN rd_out[42]
    DIRECTION OUTPUT ;
    USE SIGNAL ;
    SHAPE ABUTMENT ;
    PORT
      LAYER M4 ;
      RECT 118.776 11.616 118.800 11.640 ;
    END
  END rd_out[42]
  PIN rd_out[43]
    DIRECTION OUTPUT ;
    USE SIGNAL ;
    SHAPE ABUTMENT ;
    PORT
      LAYER M4 ;
      RECT 118.776 11.712 118.800 11.736 ;
    END
  END rd_out[43]
  PIN rd_out[44]
    DIRECTION OUTPUT ;
    USE SIGNAL ;
    SHAPE ABUTMENT ;
    PORT
      LAYER M4 ;
      RECT 118.776 11.808 118.800 11.832 ;
    END
  END rd_out[44]
  PIN rd_out[45]
    DIRECTION OUTPUT ;
    USE SIGNAL ;
    SHAPE ABUTMENT ;
    PORT
      LAYER M4 ;
      RECT 118.776 11.904 118.800 11.928 ;
    END
  END rd_out[45]
  PIN rd_out[46]
    DIRECTION OUTPUT ;
    USE SIGNAL ;
    SHAPE ABUTMENT ;
    PORT
      LAYER M4 ;
      RECT 118.776 12.000 118.800 12.024 ;
    END
  END rd_out[46]
  PIN rd_out[47]
    DIRECTION OUTPUT ;
    USE SIGNAL ;
    SHAPE ABUTMENT ;
    PORT
      LAYER M4 ;
      RECT 118.776 12.096 118.800 12.120 ;
    END
  END rd_out[47]
  PIN rd_out[48]
    DIRECTION OUTPUT ;
    USE SIGNAL ;
    SHAPE ABUTMENT ;
    PORT
      LAYER M4 ;
      RECT 118.776 12.192 118.800 12.216 ;
    END
  END rd_out[48]
  PIN rd_out[49]
    DIRECTION OUTPUT ;
    USE SIGNAL ;
    SHAPE ABUTMENT ;
    PORT
      LAYER M4 ;
      RECT 118.776 12.288 118.800 12.312 ;
    END
  END rd_out[49]
  PIN rd_out[50]
    DIRECTION OUTPUT ;
    USE SIGNAL ;
    SHAPE ABUTMENT ;
    PORT
      LAYER M4 ;
      RECT 118.776 12.384 118.800 12.408 ;
    END
  END rd_out[50]
  PIN rd_out[51]
    DIRECTION OUTPUT ;
    USE SIGNAL ;
    SHAPE ABUTMENT ;
    PORT
      LAYER M4 ;
      RECT 118.776 12.480 118.800 12.504 ;
    END
  END rd_out[51]
  PIN rd_out[52]
    DIRECTION OUTPUT ;
    USE SIGNAL ;
    SHAPE ABUTMENT ;
    PORT
      LAYER M4 ;
      RECT 118.776 12.576 118.800 12.600 ;
    END
  END rd_out[52]
  PIN rd_out[53]
    DIRECTION OUTPUT ;
    USE SIGNAL ;
    SHAPE ABUTMENT ;
    PORT
      LAYER M4 ;
      RECT 118.776 12.672 118.800 12.696 ;
    END
  END rd_out[53]
  PIN rd_out[54]
    DIRECTION OUTPUT ;
    USE SIGNAL ;
    SHAPE ABUTMENT ;
    PORT
      LAYER M4 ;
      RECT 118.776 12.768 118.800 12.792 ;
    END
  END rd_out[54]
  PIN rd_out[55]
    DIRECTION OUTPUT ;
    USE SIGNAL ;
    SHAPE ABUTMENT ;
    PORT
      LAYER M4 ;
      RECT 118.776 12.864 118.800 12.888 ;
    END
  END rd_out[55]
  PIN rd_out[56]
    DIRECTION OUTPUT ;
    USE SIGNAL ;
    SHAPE ABUTMENT ;
    PORT
      LAYER M4 ;
      RECT 118.776 12.960 118.800 12.984 ;
    END
  END rd_out[56]
  PIN rd_out[57]
    DIRECTION OUTPUT ;
    USE SIGNAL ;
    SHAPE ABUTMENT ;
    PORT
      LAYER M4 ;
      RECT 118.776 13.056 118.800 13.080 ;
    END
  END rd_out[57]
  PIN rd_out[58]
    DIRECTION OUTPUT ;
    USE SIGNAL ;
    SHAPE ABUTMENT ;
    PORT
      LAYER M4 ;
      RECT 118.776 13.152 118.800 13.176 ;
    END
  END rd_out[58]
  PIN rd_out[59]
    DIRECTION OUTPUT ;
    USE SIGNAL ;
    SHAPE ABUTMENT ;
    PORT
      LAYER M4 ;
      RECT 118.776 13.248 118.800 13.272 ;
    END
  END rd_out[59]
  PIN rd_out[60]
    DIRECTION OUTPUT ;
    USE SIGNAL ;
    SHAPE ABUTMENT ;
    PORT
      LAYER M4 ;
      RECT 118.776 13.344 118.800 13.368 ;
    END
  END rd_out[60]
  PIN rd_out[61]
    DIRECTION OUTPUT ;
    USE SIGNAL ;
    SHAPE ABUTMENT ;
    PORT
      LAYER M4 ;
      RECT 118.776 13.440 118.800 13.464 ;
    END
  END rd_out[61]
  PIN rd_out[62]
    DIRECTION OUTPUT ;
    USE SIGNAL ;
    SHAPE ABUTMENT ;
    PORT
      LAYER M4 ;
      RECT 118.776 13.536 118.800 13.560 ;
    END
  END rd_out[62]
  PIN rd_out[63]
    DIRECTION OUTPUT ;
    USE SIGNAL ;
    SHAPE ABUTMENT ;
    PORT
      LAYER M4 ;
      RECT 118.776 13.632 118.800 13.656 ;
    END
  END rd_out[63]
  PIN rd_out[64]
    DIRECTION OUTPUT ;
    USE SIGNAL ;
    SHAPE ABUTMENT ;
    PORT
      LAYER M4 ;
      RECT 118.776 13.728 118.800 13.752 ;
    END
  END rd_out[64]
  PIN rd_out[65]
    DIRECTION OUTPUT ;
    USE SIGNAL ;
    SHAPE ABUTMENT ;
    PORT
      LAYER M4 ;
      RECT 118.776 13.824 118.800 13.848 ;
    END
  END rd_out[65]
  PIN rd_out[66]
    DIRECTION OUTPUT ;
    USE SIGNAL ;
    SHAPE ABUTMENT ;
    PORT
      LAYER M4 ;
      RECT 118.776 13.920 118.800 13.944 ;
    END
  END rd_out[66]
  PIN rd_out[67]
    DIRECTION OUTPUT ;
    USE SIGNAL ;
    SHAPE ABUTMENT ;
    PORT
      LAYER M4 ;
      RECT 118.776 14.016 118.800 14.040 ;
    END
  END rd_out[67]
  PIN rd_out[68]
    DIRECTION OUTPUT ;
    USE SIGNAL ;
    SHAPE ABUTMENT ;
    PORT
      LAYER M4 ;
      RECT 118.776 14.112 118.800 14.136 ;
    END
  END rd_out[68]
  PIN rd_out[69]
    DIRECTION OUTPUT ;
    USE SIGNAL ;
    SHAPE ABUTMENT ;
    PORT
      LAYER M4 ;
      RECT 118.776 14.208 118.800 14.232 ;
    END
  END rd_out[69]
  PIN rd_out[70]
    DIRECTION OUTPUT ;
    USE SIGNAL ;
    SHAPE ABUTMENT ;
    PORT
      LAYER M4 ;
      RECT 118.776 14.304 118.800 14.328 ;
    END
  END rd_out[70]
  PIN rd_out[71]
    DIRECTION OUTPUT ;
    USE SIGNAL ;
    SHAPE ABUTMENT ;
    PORT
      LAYER M4 ;
      RECT 118.776 14.400 118.800 14.424 ;
    END
  END rd_out[71]
  PIN rd_out[72]
    DIRECTION OUTPUT ;
    USE SIGNAL ;
    SHAPE ABUTMENT ;
    PORT
      LAYER M4 ;
      RECT 118.776 14.496 118.800 14.520 ;
    END
  END rd_out[72]
  PIN rd_out[73]
    DIRECTION OUTPUT ;
    USE SIGNAL ;
    SHAPE ABUTMENT ;
    PORT
      LAYER M4 ;
      RECT 118.776 14.592 118.800 14.616 ;
    END
  END rd_out[73]
  PIN rd_out[74]
    DIRECTION OUTPUT ;
    USE SIGNAL ;
    SHAPE ABUTMENT ;
    PORT
      LAYER M4 ;
      RECT 118.776 14.688 118.800 14.712 ;
    END
  END rd_out[74]
  PIN rd_out[75]
    DIRECTION OUTPUT ;
    USE SIGNAL ;
    SHAPE ABUTMENT ;
    PORT
      LAYER M4 ;
      RECT 118.776 14.784 118.800 14.808 ;
    END
  END rd_out[75]
  PIN rd_out[76]
    DIRECTION OUTPUT ;
    USE SIGNAL ;
    SHAPE ABUTMENT ;
    PORT
      LAYER M4 ;
      RECT 118.776 14.880 118.800 14.904 ;
    END
  END rd_out[76]
  PIN rd_out[77]
    DIRECTION OUTPUT ;
    USE SIGNAL ;
    SHAPE ABUTMENT ;
    PORT
      LAYER M4 ;
      RECT 118.776 14.976 118.800 15.000 ;
    END
  END rd_out[77]
  PIN rd_out[78]
    DIRECTION OUTPUT ;
    USE SIGNAL ;
    SHAPE ABUTMENT ;
    PORT
      LAYER M4 ;
      RECT 118.776 15.072 118.800 15.096 ;
    END
  END rd_out[78]
  PIN rd_out[79]
    DIRECTION OUTPUT ;
    USE SIGNAL ;
    SHAPE ABUTMENT ;
    PORT
      LAYER M4 ;
      RECT 118.776 15.168 118.800 15.192 ;
    END
  END rd_out[79]
  PIN rd_out[80]
    DIRECTION OUTPUT ;
    USE SIGNAL ;
    SHAPE ABUTMENT ;
    PORT
      LAYER M4 ;
      RECT 118.776 15.264 118.800 15.288 ;
    END
  END rd_out[80]
  PIN rd_out[81]
    DIRECTION OUTPUT ;
    USE SIGNAL ;
    SHAPE ABUTMENT ;
    PORT
      LAYER M4 ;
      RECT 118.776 15.360 118.800 15.384 ;
    END
  END rd_out[81]
  PIN rd_out[82]
    DIRECTION OUTPUT ;
    USE SIGNAL ;
    SHAPE ABUTMENT ;
    PORT
      LAYER M4 ;
      RECT 118.776 15.456 118.800 15.480 ;
    END
  END rd_out[82]
  PIN rd_out[83]
    DIRECTION OUTPUT ;
    USE SIGNAL ;
    SHAPE ABUTMENT ;
    PORT
      LAYER M4 ;
      RECT 118.776 15.552 118.800 15.576 ;
    END
  END rd_out[83]
  PIN rd_out[84]
    DIRECTION OUTPUT ;
    USE SIGNAL ;
    SHAPE ABUTMENT ;
    PORT
      LAYER M4 ;
      RECT 118.776 15.648 118.800 15.672 ;
    END
  END rd_out[84]
  PIN rd_out[85]
    DIRECTION OUTPUT ;
    USE SIGNAL ;
    SHAPE ABUTMENT ;
    PORT
      LAYER M4 ;
      RECT 118.776 15.744 118.800 15.768 ;
    END
  END rd_out[85]
  PIN rd_out[86]
    DIRECTION OUTPUT ;
    USE SIGNAL ;
    SHAPE ABUTMENT ;
    PORT
      LAYER M4 ;
      RECT 118.776 15.840 118.800 15.864 ;
    END
  END rd_out[86]
  PIN rd_out[87]
    DIRECTION OUTPUT ;
    USE SIGNAL ;
    SHAPE ABUTMENT ;
    PORT
      LAYER M4 ;
      RECT 118.776 15.936 118.800 15.960 ;
    END
  END rd_out[87]
  PIN rd_out[88]
    DIRECTION OUTPUT ;
    USE SIGNAL ;
    SHAPE ABUTMENT ;
    PORT
      LAYER M4 ;
      RECT 118.776 16.032 118.800 16.056 ;
    END
  END rd_out[88]
  PIN rd_out[89]
    DIRECTION OUTPUT ;
    USE SIGNAL ;
    SHAPE ABUTMENT ;
    PORT
      LAYER M4 ;
      RECT 118.776 16.128 118.800 16.152 ;
    END
  END rd_out[89]
  PIN rd_out[90]
    DIRECTION OUTPUT ;
    USE SIGNAL ;
    SHAPE ABUTMENT ;
    PORT
      LAYER M4 ;
      RECT 118.776 16.224 118.800 16.248 ;
    END
  END rd_out[90]
  PIN rd_out[91]
    DIRECTION OUTPUT ;
    USE SIGNAL ;
    SHAPE ABUTMENT ;
    PORT
      LAYER M4 ;
      RECT 118.776 16.320 118.800 16.344 ;
    END
  END rd_out[91]
  PIN rd_out[92]
    DIRECTION OUTPUT ;
    USE SIGNAL ;
    SHAPE ABUTMENT ;
    PORT
      LAYER M4 ;
      RECT 118.776 16.416 118.800 16.440 ;
    END
  END rd_out[92]
  PIN rd_out[93]
    DIRECTION OUTPUT ;
    USE SIGNAL ;
    SHAPE ABUTMENT ;
    PORT
      LAYER M4 ;
      RECT 118.776 16.512 118.800 16.536 ;
    END
  END rd_out[93]
  PIN rd_out[94]
    DIRECTION OUTPUT ;
    USE SIGNAL ;
    SHAPE ABUTMENT ;
    PORT
      LAYER M4 ;
      RECT 118.776 16.608 118.800 16.632 ;
    END
  END rd_out[94]
  PIN rd_out[95]
    DIRECTION OUTPUT ;
    USE SIGNAL ;
    SHAPE ABUTMENT ;
    PORT
      LAYER M4 ;
      RECT 118.776 16.704 118.800 16.728 ;
    END
  END rd_out[95]
  PIN rd_out[96]
    DIRECTION OUTPUT ;
    USE SIGNAL ;
    SHAPE ABUTMENT ;
    PORT
      LAYER M4 ;
      RECT 118.776 16.800 118.800 16.824 ;
    END
  END rd_out[96]
  PIN rd_out[97]
    DIRECTION OUTPUT ;
    USE SIGNAL ;
    SHAPE ABUTMENT ;
    PORT
      LAYER M4 ;
      RECT 118.776 16.896 118.800 16.920 ;
    END
  END rd_out[97]
  PIN rd_out[98]
    DIRECTION OUTPUT ;
    USE SIGNAL ;
    SHAPE ABUTMENT ;
    PORT
      LAYER M4 ;
      RECT 118.776 16.992 118.800 17.016 ;
    END
  END rd_out[98]
  PIN rd_out[99]
    DIRECTION OUTPUT ;
    USE SIGNAL ;
    SHAPE ABUTMENT ;
    PORT
      LAYER M4 ;
      RECT 118.776 17.088 118.800 17.112 ;
    END
  END rd_out[99]
  PIN rd_out[100]
    DIRECTION OUTPUT ;
    USE SIGNAL ;
    SHAPE ABUTMENT ;
    PORT
      LAYER M4 ;
      RECT 118.776 17.184 118.800 17.208 ;
    END
  END rd_out[100]
  PIN rd_out[101]
    DIRECTION OUTPUT ;
    USE SIGNAL ;
    SHAPE ABUTMENT ;
    PORT
      LAYER M4 ;
      RECT 118.776 17.280 118.800 17.304 ;
    END
  END rd_out[101]
  PIN rd_out[102]
    DIRECTION OUTPUT ;
    USE SIGNAL ;
    SHAPE ABUTMENT ;
    PORT
      LAYER M4 ;
      RECT 118.776 17.376 118.800 17.400 ;
    END
  END rd_out[102]
  PIN rd_out[103]
    DIRECTION OUTPUT ;
    USE SIGNAL ;
    SHAPE ABUTMENT ;
    PORT
      LAYER M4 ;
      RECT 118.776 17.472 118.800 17.496 ;
    END
  END rd_out[103]
  PIN rd_out[104]
    DIRECTION OUTPUT ;
    USE SIGNAL ;
    SHAPE ABUTMENT ;
    PORT
      LAYER M4 ;
      RECT 118.776 17.568 118.800 17.592 ;
    END
  END rd_out[104]
  PIN rd_out[105]
    DIRECTION OUTPUT ;
    USE SIGNAL ;
    SHAPE ABUTMENT ;
    PORT
      LAYER M4 ;
      RECT 118.776 17.664 118.800 17.688 ;
    END
  END rd_out[105]
  PIN rd_out[106]
    DIRECTION OUTPUT ;
    USE SIGNAL ;
    SHAPE ABUTMENT ;
    PORT
      LAYER M4 ;
      RECT 118.776 17.760 118.800 17.784 ;
    END
  END rd_out[106]
  PIN rd_out[107]
    DIRECTION OUTPUT ;
    USE SIGNAL ;
    SHAPE ABUTMENT ;
    PORT
      LAYER M4 ;
      RECT 118.776 17.856 118.800 17.880 ;
    END
  END rd_out[107]
  PIN rd_out[108]
    DIRECTION OUTPUT ;
    USE SIGNAL ;
    SHAPE ABUTMENT ;
    PORT
      LAYER M4 ;
      RECT 118.776 17.952 118.800 17.976 ;
    END
  END rd_out[108]
  PIN rd_out[109]
    DIRECTION OUTPUT ;
    USE SIGNAL ;
    SHAPE ABUTMENT ;
    PORT
      LAYER M4 ;
      RECT 118.776 18.048 118.800 18.072 ;
    END
  END rd_out[109]
  PIN rd_out[110]
    DIRECTION OUTPUT ;
    USE SIGNAL ;
    SHAPE ABUTMENT ;
    PORT
      LAYER M4 ;
      RECT 118.776 18.144 118.800 18.168 ;
    END
  END rd_out[110]
  PIN rd_out[111]
    DIRECTION OUTPUT ;
    USE SIGNAL ;
    SHAPE ABUTMENT ;
    PORT
      LAYER M4 ;
      RECT 118.776 18.240 118.800 18.264 ;
    END
  END rd_out[111]
  PIN rd_out[112]
    DIRECTION OUTPUT ;
    USE SIGNAL ;
    SHAPE ABUTMENT ;
    PORT
      LAYER M4 ;
      RECT 118.776 18.336 118.800 18.360 ;
    END
  END rd_out[112]
  PIN rd_out[113]
    DIRECTION OUTPUT ;
    USE SIGNAL ;
    SHAPE ABUTMENT ;
    PORT
      LAYER M4 ;
      RECT 118.776 18.432 118.800 18.456 ;
    END
  END rd_out[113]
  PIN rd_out[114]
    DIRECTION OUTPUT ;
    USE SIGNAL ;
    SHAPE ABUTMENT ;
    PORT
      LAYER M4 ;
      RECT 118.776 18.528 118.800 18.552 ;
    END
  END rd_out[114]
  PIN rd_out[115]
    DIRECTION OUTPUT ;
    USE SIGNAL ;
    SHAPE ABUTMENT ;
    PORT
      LAYER M4 ;
      RECT 118.776 18.624 118.800 18.648 ;
    END
  END rd_out[115]
  PIN rd_out[116]
    DIRECTION OUTPUT ;
    USE SIGNAL ;
    SHAPE ABUTMENT ;
    PORT
      LAYER M4 ;
      RECT 118.776 18.720 118.800 18.744 ;
    END
  END rd_out[116]
  PIN rd_out[117]
    DIRECTION OUTPUT ;
    USE SIGNAL ;
    SHAPE ABUTMENT ;
    PORT
      LAYER M4 ;
      RECT 118.776 18.816 118.800 18.840 ;
    END
  END rd_out[117]
  PIN rd_out[118]
    DIRECTION OUTPUT ;
    USE SIGNAL ;
    SHAPE ABUTMENT ;
    PORT
      LAYER M4 ;
      RECT 118.776 18.912 118.800 18.936 ;
    END
  END rd_out[118]
  PIN rd_out[119]
    DIRECTION OUTPUT ;
    USE SIGNAL ;
    SHAPE ABUTMENT ;
    PORT
      LAYER M4 ;
      RECT 118.776 19.008 118.800 19.032 ;
    END
  END rd_out[119]
  PIN rd_out[120]
    DIRECTION OUTPUT ;
    USE SIGNAL ;
    SHAPE ABUTMENT ;
    PORT
      LAYER M4 ;
      RECT 118.776 19.104 118.800 19.128 ;
    END
  END rd_out[120]
  PIN rd_out[121]
    DIRECTION OUTPUT ;
    USE SIGNAL ;
    SHAPE ABUTMENT ;
    PORT
      LAYER M4 ;
      RECT 118.776 19.200 118.800 19.224 ;
    END
  END rd_out[121]
  PIN rd_out[122]
    DIRECTION OUTPUT ;
    USE SIGNAL ;
    SHAPE ABUTMENT ;
    PORT
      LAYER M4 ;
      RECT 118.776 19.296 118.800 19.320 ;
    END
  END rd_out[122]
  PIN rd_out[123]
    DIRECTION OUTPUT ;
    USE SIGNAL ;
    SHAPE ABUTMENT ;
    PORT
      LAYER M4 ;
      RECT 118.776 19.392 118.800 19.416 ;
    END
  END rd_out[123]
  PIN rd_out[124]
    DIRECTION OUTPUT ;
    USE SIGNAL ;
    SHAPE ABUTMENT ;
    PORT
      LAYER M4 ;
      RECT 118.776 19.488 118.800 19.512 ;
    END
  END rd_out[124]
  PIN rd_out[125]
    DIRECTION OUTPUT ;
    USE SIGNAL ;
    SHAPE ABUTMENT ;
    PORT
      LAYER M4 ;
      RECT 118.776 19.584 118.800 19.608 ;
    END
  END rd_out[125]
  PIN rd_out[126]
    DIRECTION OUTPUT ;
    USE SIGNAL ;
    SHAPE ABUTMENT ;
    PORT
      LAYER M4 ;
      RECT 118.776 19.680 118.800 19.704 ;
    END
  END rd_out[126]
  PIN rd_out[127]
    DIRECTION OUTPUT ;
    USE SIGNAL ;
    SHAPE ABUTMENT ;
    PORT
      LAYER M4 ;
      RECT 118.776 19.776 118.800 19.800 ;
    END
  END rd_out[127]
  PIN VDD
    DIRECTION INOUT ;
    USE POWER ;
    PORT
      LAYER M4 ;
      RECT 0.300 0.384 118.500 0.480 ;
      RECT 0.300 1.152 118.500 1.248 ;
      RECT 0.300 1.920 118.500 2.016 ;
      RECT 0.300 2.688 118.500 2.784 ;
      RECT 0.300 3.456 118.500 3.552 ;
      RECT 0.300 4.224 118.500 4.320 ;
      RECT 0.300 4.992 118.500 5.088 ;
      RECT 0.300 5.760 118.500 5.856 ;
      RECT 0.300 6.528 118.500 6.624 ;
      RECT 0.300 7.296 118.500 7.392 ;
      RECT 0.300 8.064 118.500 8.160 ;
      RECT 0.300 8.832 118.500 8.928 ;
      RECT 0.300 9.600 118.500 9.696 ;
      RECT 0.300 10.368 118.500 10.464 ;
      RECT 0.300 11.136 118.500 11.232 ;
      RECT 0.300 11.904 118.500 12.000 ;
      RECT 0.300 12.672 118.500 12.768 ;
      RECT 0.300 13.440 118.500 13.536 ;
      RECT 0.300 14.208 118.500 14.304 ;
      RECT 0.300 14.976 118.500 15.072 ;
      RECT 0.300 15.744 118.500 15.840 ;
      RECT 0.300 16.512 118.500 16.608 ;
      RECT 0.300 17.280 118.500 17.376 ;
      RECT 0.300 18.048 118.500 18.144 ;
      RECT 0.300 18.816 118.500 18.912 ;
      RECT 0.300 19.584 118.500 19.680 ;
      RECT 0.300 20.352 118.500 20.448 ;
      RECT 0.300 21.120 118.500 21.216 ;
      RECT 0.300 21.888 118.500 21.984 ;
      RECT 0.300 22.656 118.500 22.752 ;
      RECT 0.300 23.424 118.500 23.520 ;
      RECT 0.300 24.192 118.500 24.288 ;
      RECT 0.300 24.960 118.500 25.056 ;
      RECT 0.300 25.728 118.500 25.824 ;
      RECT 0.300 26.496 118.500 26.592 ;
      RECT 0.300 27.264 118.500 27.360 ;
      RECT 0.300 28.032 118.500 28.128 ;
      RECT 0.300 28.800 118.500 28.896 ;
      RECT 0.300 29.568 118.500 29.664 ;
      RECT 0.300 30.336 118.500 30.432 ;
      RECT 0.300 31.104 118.500 31.200 ;
      RECT 0.300 31.872 118.500 31.968 ;
      RECT 0.300 32.640 118.500 32.736 ;
      RECT 0.300 33.408 118.500 33.504 ;
      RECT 0.300 34.176 118.500 34.272 ;
      RECT 0.300 34.944 118.500 35.040 ;
      RECT 0.300 35.712 118.500 35.808 ;
      RECT 0.300 36.480 118.500 36.576 ;
      RECT 0.300 37.248 118.500 37.344 ;
      RECT 0.300 38.016 118.500 38.112 ;
      RECT 0.300 38.784 118.500 38.880 ;
      RECT 0.300 39.552 118.500 39.648 ;
      RECT 0.300 40.320 118.500 40.416 ;
      RECT 0.300 41.088 118.500 41.184 ;
      RECT 0.300 41.856 118.500 41.952 ;
      RECT 0.300 42.624 118.500 42.720 ;
      RECT 0.300 43.392 118.500 43.488 ;
      RECT 0.300 44.160 118.500 44.256 ;
      RECT 0.300 44.928 118.500 45.024 ;
      RECT 0.300 45.696 118.500 45.792 ;
      RECT 0.300 46.464 118.500 46.560 ;
      RECT 0.300 47.232 118.500 47.328 ;
      RECT 0.300 48.000 118.500 48.096 ;
      RECT 0.300 48.768 118.500 48.864 ;
      RECT 0.300 49.536 118.500 49.632 ;
      RECT 0.300 50.304 118.500 50.400 ;
      RECT 0.300 51.072 118.500 51.168 ;
      RECT 0.300 51.840 118.500 51.936 ;
      RECT 0.300 52.608 118.500 52.704 ;
      RECT 0.300 53.376 118.500 53.472 ;
      RECT 0.300 54.144 118.500 54.240 ;
      RECT 0.300 54.912 118.500 55.008 ;
      RECT 0.300 55.680 118.500 55.776 ;
      RECT 0.300 56.448 118.500 56.544 ;
      RECT 0.300 57.216 118.500 57.312 ;
      RECT 0.300 57.984 118.500 58.080 ;
      RECT 0.300 58.752 118.500 58.848 ;
      RECT 0.300 59.520 118.500 59.616 ;
      RECT 0.300 60.288 118.500 60.384 ;
      RECT 0.300 61.056 118.500 61.152 ;
      RECT 0.300 61.824 118.500 61.920 ;
      RECT 0.300 62.592 118.500 62.688 ;
      RECT 0.300 63.360 118.500 63.456 ;
      RECT 0.300 64.128 118.500 64.224 ;
      RECT 0.300 64.896 118.500 64.992 ;
    END
  END VDD
  PIN VSS
    DIRECTION INOUT ;
    USE GROUND ;
    PORT
      LAYER M4 ;
      RECT 0.300 0.768 118.500 0.864 ;
      RECT 0.300 1.536 118.500 1.632 ;
      RECT 0.300 2.304 118.500 2.400 ;
      RECT 0.300 3.072 118.500 3.168 ;
      RECT 0.300 3.840 118.500 3.936 ;
      RECT 0.300 4.608 118.500 4.704 ;
      RECT 0.300 5.376 118.500 5.472 ;
      RECT 0.300 6.144 118.500 6.240 ;
      RECT 0.300 6.912 118.500 7.008 ;
      RECT 0.300 7.680 118.500 7.776 ;
      RECT 0.300 8.448 118.500 8.544 ;
      RECT 0.300 9.216 118.500 9.312 ;
      RECT 0.300 9.984 118.500 10.080 ;
      RECT 0.300 10.752 118.500 10.848 ;
      RECT 0.300 11.520 118.500 11.616 ;
      RECT 0.300 12.288 118.500 12.384 ;
      RECT 0.300 13.056 118.500 13.152 ;
      RECT 0.300 13.824 118.500 13.920 ;
      RECT 0.300 14.592 118.500 14.688 ;
      RECT 0.300 15.360 118.500 15.456 ;
      RECT 0.300 16.128 118.500 16.224 ;
      RECT 0.300 16.896 118.500 16.992 ;
      RECT 0.300 17.664 118.500 17.760 ;
      RECT 0.300 18.432 118.500 18.528 ;
      RECT 0.300 19.200 118.500 19.296 ;
      RECT 0.300 19.968 118.500 20.064 ;
      RECT 0.300 20.736 118.500 20.832 ;
      RECT 0.300 21.504 118.500 21.600 ;
      RECT 0.300 22.272 118.500 22.368 ;
      RECT 0.300 23.040 118.500 23.136 ;
      RECT 0.300 23.808 118.500 23.904 ;
      RECT 0.300 24.576 118.500 24.672 ;
      RECT 0.300 25.344 118.500 25.440 ;
      RECT 0.300 26.112 118.500 26.208 ;
      RECT 0.300 26.880 118.500 26.976 ;
      RECT 0.300 27.648 118.500 27.744 ;
      RECT 0.300 28.416 118.500 28.512 ;
      RECT 0.300 29.184 118.500 29.280 ;
      RECT 0.300 29.952 118.500 30.048 ;
      RECT 0.300 30.720 118.500 30.816 ;
      RECT 0.300 31.488 118.500 31.584 ;
      RECT 0.300 32.256 118.500 32.352 ;
      RECT 0.300 33.024 118.500 33.120 ;
      RECT 0.300 33.792 118.500 33.888 ;
      RECT 0.300 34.560 118.500 34.656 ;
      RECT 0.300 35.328 118.500 35.424 ;
      RECT 0.300 36.096 118.500 36.192 ;
      RECT 0.300 36.864 118.500 36.960 ;
      RECT 0.300 37.632 118.500 37.728 ;
      RECT 0.300 38.400 118.500 38.496 ;
      RECT 0.300 39.168 118.500 39.264 ;
      RECT 0.300 39.936 118.500 40.032 ;
      RECT 0.300 40.704 118.500 40.800 ;
      RECT 0.300 41.472 118.500 41.568 ;
      RECT 0.300 42.240 118.500 42.336 ;
      RECT 0.300 43.008 118.500 43.104 ;
      RECT 0.300 43.776 118.500 43.872 ;
      RECT 0.300 44.544 118.500 44.640 ;
      RECT 0.300 45.312 118.500 45.408 ;
      RECT 0.300 46.080 118.500 46.176 ;
      RECT 0.300 46.848 118.500 46.944 ;
      RECT 0.300 47.616 118.500 47.712 ;
      RECT 0.300 48.384 118.500 48.480 ;
      RECT 0.300 49.152 118.500 49.248 ;
      RECT 0.300 49.920 118.500 50.016 ;
      RECT 0.300 50.688 118.500 50.784 ;
      RECT 0.300 51.456 118.500 51.552 ;
      RECT 0.300 52.224 118.500 52.320 ;
      RECT 0.300 52.992 118.500 53.088 ;
      RECT 0.300 53.760 118.500 53.856 ;
      RECT 0.300 54.528 118.500 54.624 ;
      RECT 0.300 55.296 118.500 55.392 ;
      RECT 0.300 56.064 118.500 56.160 ;
      RECT 0.300 56.832 118.500 56.928 ;
      RECT 0.300 57.600 118.500 57.696 ;
      RECT 0.300 58.368 118.500 58.464 ;
      RECT 0.300 59.136 118.500 59.232 ;
      RECT 0.300 59.904 118.500 60.000 ;
      RECT 0.300 60.672 118.500 60.768 ;
      RECT 0.300 61.440 118.500 61.536 ;
      RECT 0.300 62.208 118.500 62.304 ;
      RECT 0.300 62.976 118.500 63.072 ;
      RECT 0.300 63.744 118.500 63.840 ;
      RECT 0.300 64.512 118.500 64.608 ;
      RECT 0.300 65.280 118.500 65.376 ;
    END
  END VSS
  OBS
    LAYER M1 ;
    RECT 0 0 118.800 65.610 ;
    LAYER M2 ;
    RECT 0 0 118.800 65.610 ;
    LAYER M3 ;
    RECT 0 0 118.800 65.610 ;
    LAYER M4 ;
    RECT 0.072 0 118.728 65.610 ;
  END
END ot_sram_1rw_2048x128_m4

END LIBRARY
